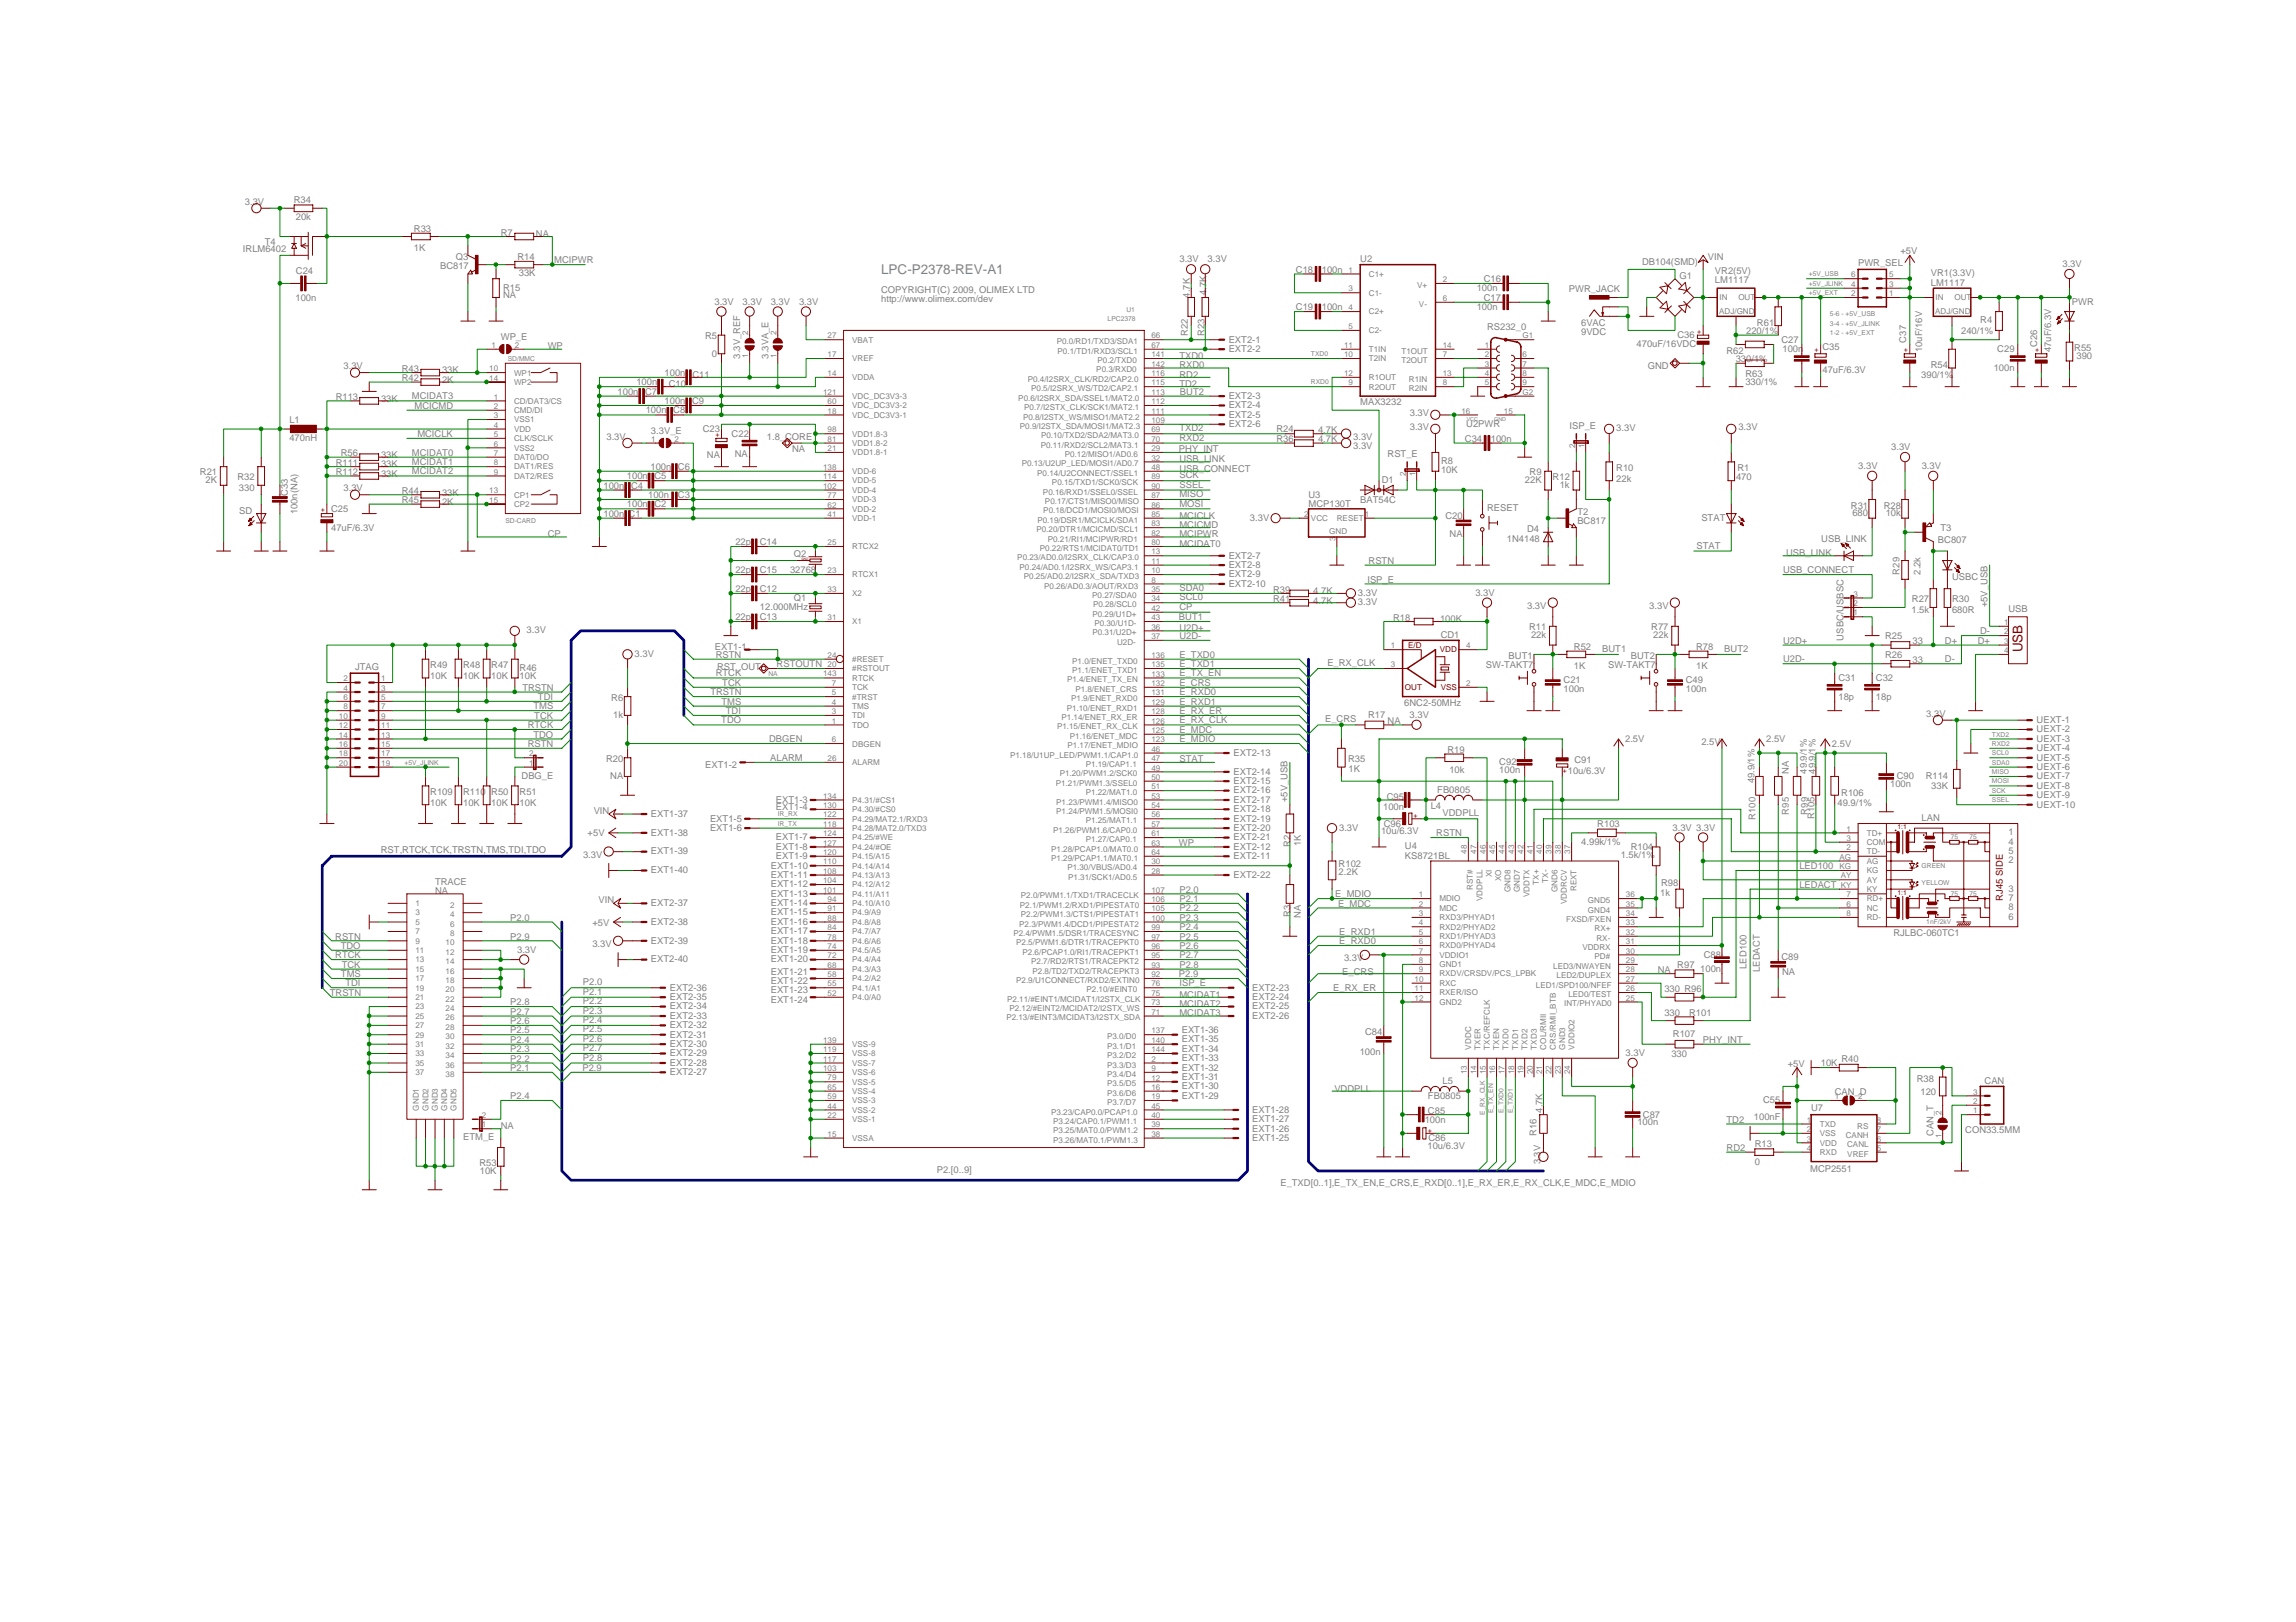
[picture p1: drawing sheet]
<svg xmlns="http://www.w3.org/2000/svg" width="297mm" height="210mm" viewBox="0 0 297 210" stroke-linecap="round" stroke-linejoin="round" font-family="sans-serif">
<defs><g id="words">
<text font-size="1.7" fill="#808080" x="114" y="35.5">LPC-P2378-REV-A1</text>
<text font-size="1.7" fill="#800000" x="261.7" y="84.4" transform="rotate(-90 261.7 84.4)">USB</text>
<g font-size="1.2" fill="#808080">
<text x="31.7" y="26.5">3.3V</text>
<text x="38" y="26.2">R34</text>
<text x="38.3" y="28.5">20k</text>
<text x="53.5" y="30">R33</text>
<text x="31.4" y="32.6">IRLM6402</text>
<text x="34.3" y="31.7">T4</text>
<text x="38.3" y="35.5">C24</text>
<text x="53.5" y="32.5">1K</text>
<text x="56.9" y="34.9">BC817</text>
<text x="59" y="33.6">Q3</text>
<text x="64.8" y="30.5">R7</text>
<text x="66.9" y="33.7">R14</text>
<text x="67.1" y="35.7">33K</text>
<text x="69.3" y="30.7">NA</text>
<text x="71.7" y="34">MCIPWR</text>
<text x="152.6" y="34">3.3V</text>
<text x="156.2" y="34">3.3V</text>
<text x="167.7" y="35.3">C18</text>
<text x="171" y="35.3">100n</text>
<text x="176" y="34">U2</text>
<text x="212.4" y="34.2">DB104(SMD)</text>
<text x="221" y="33.6">VIN</text>
<text x="221.9" y="35.5">VR2(5V)</text>
<text x="240.4" y="34.5">PWR_SEL</text>
<text x="245.9" y="32.9">+5V</text>
<text x="249.8" y="35.8">VR1(3.3V)</text>
<text x="266.8" y="34.5">3.3V</text>
<text x="38.2" y="38.9">100n</text>
<text x="65.1" y="37.6">R15</text>
<text x="65.1" y="38.6">NA</text>
<text x="92.4" y="39.4">3.3V</text>
<text x="96.1" y="39.4">3.3V</text>
<text x="99.7" y="39.4">3.3V</text>
<text x="103.4" y="39.4">3.3V</text>
<text x="114" y="37.9">COPYRIGHT(C) 2009, OLIMEX LTD</text>
<text x="114" y="39.1">http://www.olimex.com/dev</text>
<text x="153.9" y="38.5" transform="rotate(-90 153.9 38.5)">4.7K</text>
<text x="156.1" y="38.2" transform="rotate(-90 156.1 38.2)">4.7K</text>
<text x="167.7" y="40.1">C19</text>
<text x="171" y="40.1">100n</text>
<text x="191" y="37.7">100n</text>
<text x="191" y="40.1">100n</text>
<text x="192" y="36.5">C16</text>
<text x="192" y="38.9">C17</text>
<text x="203" y="37.8">PWR_JACK</text>
<text x="217.3" y="36.1">G1</text>
<text x="221.9" y="36.7">LM1117</text>
<text x="249.8" y="37">LM1117</text>
<text x="256.2" y="41.8">R4</text>
<text x="268.1" y="39.4">PWR</text>
<text x="44.4" y="47.8">3.3V</text>
<text x="64.8" y="44">WP_E</text>
<text x="70.9" y="45.2">WP</text>
<text x="91.2" y="43.9">R5</text>
<text x="92.1" y="46.2">0</text>
<text x="95.8" y="46.4" transform="rotate(-90 95.8 46.4)">3.3V_REF</text>
<text x="99.4" y="46.4" transform="rotate(-90 99.4 46.4)">3.3VA_E</text>
<text x="152.6" y="47.7">RXD0</text>
<text x="152.6" y="46.4">TXD0</text>
<text x="153.7" y="43.5" transform="rotate(-90 153.7 43.5)">R22</text>
<text x="155.8" y="43.5" transform="rotate(-90 155.8 43.5)">R23</text>
<text x="159" y="44.3">EXT2-1</text>
<text x="159" y="45.6">EXT2-2</text>
<text x="192.4" y="42.8">RS232_0</text>
<text x="204.6" y="42.1">6VAC</text>
<text x="204.6" y="43.4">9VDC</text>
<text x="211.7" y="45">470uF/16VDC</text>
<text x="213.2" y="47.8">GND</text>
<text x="217" y="43.7">C36</text>
<text x="223.3" y="45.8">R62</text>
<text x="224.6" y="46.8">330/1%</text>
<text x="225.9" y="43.2">220/1%</text>
<text x="227.3" y="42.2">R61</text>
<text x="230.5" y="44.4">C27</text>
<text x="230.6" y="45.6">100n</text>
<text x="235.8" y="45.3">C35</text>
<text x="246.6" y="44.3" transform="rotate(-90 246.6 44.3)">C37</text>
<text x="248.7" y="45.6" transform="rotate(-90 248.7 45.6)">10uF/16V</text>
<text x="249.8" y="47.6">R54</text>
<text x="253.7" y="43.2">240/1%</text>
<text x="258.4" y="45.6">C29</text>
<text x="263.6" y="44.9" transform="rotate(-90 263.6 44.9)">C26</text>
<text x="265.4" y="45.6" transform="rotate(-90 265.4 45.6)">47uF/6.3V</text>
<text x="268.3" y="45.4">R55</text>
<text x="268.6" y="46.5">390</text>
<text x="43.4" y="51.8">R113</text>
<text x="49.3" y="52">33K</text>
<text x="52" y="49.3">R42</text>
<text x="52" y="48.1">R43</text>
<text x="53.3" y="51.7">MCIDAT3</text>
<text x="53.6" y="52.9">MCICMD</text>
<text x="57.2" y="49.6">2K</text>
<text x="57.2" y="48.3">33K</text>
<text x="79.9" y="51.1">100n C7</text>
<text x="82.3" y="49.9">100n</text>
<text x="83.5" y="53.5">100n C8</text>
<text x="86" y="52.3">100n C9</text>
<text x="86" y="48.6">100n</text>
<text x="86.5" y="50.1">C10</text>
<text x="89.6" y="48.9">C11</text>
<text x="152.6" y="50.1">TD2</text>
<text x="152.6" y="48.9">RD2</text>
<text x="152.7" y="51.1">BUT2</text>
<text x="159" y="51.6">EXT2-3</text>
<text x="159" y="52.9">EXT2-4</text>
<text x="176" y="52.5">MAX3232</text>
<text x="182.4" y="53.9">3.3V</text>
<text x="225.8" y="49.8">330/1%</text>
<text x="225.8" y="48.8">R63</text>
<text x="235.8" y="48.3">47uF/6.3V</text>
<text x="248.6" y="48.9">390/1%</text>
<text x="257.9" y="48">100n</text>
<text x="37.4" y="57.1">470nH</text>
<text x="37.4" y="54.8">L1</text>
<text x="44.1" y="59.1">R56</text>
<text x="49.3" y="59.3">33K</text>
<text x="53.3" y="59">MCIDAT0</text>
<text x="54" y="56.6">MCICLK</text>
<text x="78.5" y="56.9">3.3V</text>
<text x="84.2" y="56.1">3.3V_E</text>
<text x="90.9" y="56">C23</text>
<text x="91.5" y="59.3">NA</text>
<text x="94.7" y="56.6">C22</text>
<text x="95.1" y="59.1">NA</text>
<text x="99.2" y="56.9">1.8_CORE</text>
<text x="102.5" y="58.5">NA</text>
<text x="152.5" y="58.4">PHY_INT</text>
<text x="152.6" y="57">RXD2</text>
<text x="152.6" y="55.8">TXD2</text>
<text x="152.6" y="59.8">USB_LINK</text>
<text x="159" y="54.1">EXT2-5</text>
<text x="159" y="55.3">EXT2-6</text>
<text x="165.1" y="57.2">R36</text>
<text x="165.1" y="56">R24</text>
<text x="170.5" y="57.2">4.7K</text>
<text x="170.5" y="56">4.7K</text>
<text x="175.1" y="56.9">3.3V</text>
<text x="175.1" y="58.1">3.3V</text>
<text x="179.5" y="59.2">RST_E</text>
<text x="182.4" y="55.7">3.3V</text>
<text x="189.5" y="57.1">C34</text>
<text x="189.7" y="55.3">U2PWR</text>
<text x="192.9" y="57.1">100n</text>
<text x="203" y="55.5">ISP_E</text>
<text x="209.1" y="55.8">3.3V</text>
<text x="224.9" y="55.7">3.3V</text>
<text x="244.7" y="58.3">3.3V</text>
<text x="25.9" y="61.5">R21</text>
<text x="26.6" y="62.6">2K</text>
<text x="30.7" y="62.2">R32</text>
<text x="30.9" y="63.5">330</text>
<text x="37.2" y="64.2" transform="rotate(-90 37.2 64.2)">C33</text>
<text x="43.4" y="60.3">R111</text>
<text x="43.4" y="61.5">R112</text>
<text x="44.4" y="63.6">3.3V</text>
<text x="49.3" y="60.5">33K</text>
<text x="49.3" y="61.7">33K</text>
<text x="52" y="63.9">R44</text>
<text x="52" y="65.1">R45</text>
<text x="53.3" y="60.2">MCIDAT1</text>
<text x="53.3" y="61.4">MCIDAT2</text>
<text x="57.2" y="64.1">33K</text>
<text x="57.2" y="65.3">2K</text>
<text x="78.1" y="63.2">100n C4</text>
<text x="81.1" y="65.7">100n C2</text>
<text x="81.1" y="62">100n C5</text>
<text x="83.9" y="64.5">100n</text>
<text x="84.2" y="60.8">100n C6</text>
<text x="87.7" y="64.5">C3</text>
<text x="152.6" y="64.3">MISO</text>
<text x="152.6" y="65.6">MOSI</text>
<text x="152.6" y="61.9">SCK</text>
<text x="152.6" y="63.1">SSEL</text>
<text x="152.6" y="61">USB_CONNECT</text>
<text x="169.3" y="65.6">MCP130T</text>
<text x="169.3" y="64.4">U3</text>
<text x="176" y="65.1">BAT54C</text>
<text x="178.8" y="62.6">D1</text>
<text x="186.4" y="60">R8</text>
<text x="186.4" y="61.2">10K</text>
<text x="197.3" y="62.6">22K</text>
<text x="197.9" y="61.5">R9</text>
<text x="200.9" y="62.1">R12</text>
<text x="201.8" y="63.2">1k</text>
<text x="209.1" y="61">R10</text>
<text x="209.1" y="62.3">22k</text>
<text x="224.6" y="62.1">470</text>
<text x="224.8" y="61">R1</text>
<text x="239.5" y="65.8">R31</text>
<text x="240.4" y="60.7">3.3V</text>
<text x="243.7" y="65.8">R28</text>
<text x="248.6" y="60.7">3.3V</text>
<text x="30.9" y="66.6">SD</text>
<text x="38.5" y="66.6" transform="rotate(-90 38.5 66.6)">100n(NA)</text>
<text x="42.8" y="68.7">47uF/6.3V</text>
<text x="42.8" y="66.2">C25</text>
<text x="70.9" y="69.5">CP</text>
<text x="78.1" y="66.9">100n C1</text>
<text x="95.1" y="70.5">22p</text>
<text x="98.3" y="70.5">C14</text>
<text x="152.6" y="70.8">MCIDAT0</text>
<text x="152.6" y="67.1">MCICLK</text>
<text x="152.6" y="68.3">MCICMD</text>
<text x="152.6" y="69.5">MCIPWR</text>
<text x="161.7" y="67.4">3.3V</text>
<text x="187" y="67.1">C20</text>
<text x="187.5" y="69.5">NA</text>
<text x="192.4" y="66.1">RESET</text>
<text x="194.9" y="70.1">1N4148</text>
<text x="197.6" y="68.9">D4</text>
<text x="204.1" y="66.6">T2</text>
<text x="204.1" y="67.9">BC817</text>
<text x="219.5" y="71.1">STAT</text>
<text x="220.1" y="67.5">STAT</text>
<text x="231.1" y="72">USB_LINK</text>
<text x="235.6" y="70.1">USB_LINK</text>
<text x="239.6" y="66.8">680</text>
<text x="244" y="66.8">10k</text>
<text x="250.7" y="70.3">BC807</text>
<text x="251" y="68.7">T3</text>
<text x="95.1" y="76.6">22p</text>
<text x="95.1" y="74.2">22p</text>
<text x="98.3" y="76.6">C12</text>
<text x="98.3" y="74.2">C15</text>
<text x="102.2" y="74.2">32768</text>
<text x="102.7" y="77.8">Q1</text>
<text x="102.7" y="72.1">Q2</text>
<text x="152.6" y="77.7">SCL0</text>
<text x="152.6" y="76.5">SDA0</text>
<text x="159" y="72.3">EXT2-7</text>
<text x="159" y="73.5">EXT2-8</text>
<text x="159" y="74.7">EXT2-9</text>
<text x="159" y="75.9">EXT2-10</text>
<text x="164.7" y="76.7">R39</text>
<text x="164.7" y="77.9">R41</text>
<text x="169.9" y="76.9">4.7K</text>
<text x="175.7" y="77.1">3.3V</text>
<text x="176.9" y="75.4">ISP_E</text>
<text x="177.1" y="73">RSTN</text>
<text x="190.9" y="77.1">3.3V</text>
<text x="230.7" y="74.2">USB_CONNECT</text>
<text x="245.8" y="74.4" transform="rotate(-90 245.8 74.4)">R29</text>
<text x="247.4" y="77.9">R27</text>
<text x="248.5" y="74.4" transform="rotate(-90 248.5 74.4)">2.2k</text>
<text x="252.5" y="75.1">USBC</text>
<text x="252.5" y="77.9">R30</text>
<text x="68.1" y="82">3.3V</text>
<text x="95.1" y="80.2">22p</text>
<text x="98.3" y="80.2">C13</text>
<text x="98.3" y="78.9">12.000MHz</text>
<text x="152.5" y="80.2">BUT1</text>
<text x="152.6" y="81.7">U2D+</text>
<text x="152.6" y="82.7">U2D-</text>
<text x="152.6" y="78.9">CP</text>
<text x="169.9" y="78.1">4.7K</text>
<text x="175.7" y="78.3">3.3V</text>
<text x="180.2" y="80.4">R18</text>
<text x="186.3" y="80.5">100K</text>
<text x="186.4" y="82.5">CD1</text>
<text x="197.6" y="78.8">3.3V</text>
<text x="197.8" y="81.5">R11</text>
<text x="198.1" y="82.6">22k</text>
<text x="213.4" y="78.8">3.3V</text>
<text x="213.6" y="81.5">R77</text>
<text x="213.9" y="82.6">22k</text>
<text x="230.7" y="83.3">U2D+</text>
<text x="238.5" y="82.9" transform="rotate(-90 238.5 82.9)">USBC/USBSC</text>
<text x="243.9" y="82.7">R25</text>
<text x="247.3" y="79.3">1.5k</text>
<text x="247.4" y="83.3">33</text>
<text x="251.6" y="83.3">D+</text>
<text x="252.5" y="79.3">680R</text>
<text x="255.9" y="83.3">D+</text>
<text x="256.2" y="82.1">D-</text>
<text x="257.1" y="78.6" transform="rotate(-90 257.1 78.6)">+5V_USB</text>
<text x="259.8" y="79.2">USB</text>
<text x="45.9" y="86.7">JTAG</text>
<text x="55.7" y="86.5">R49</text>
<text x="55.7" y="87.8">10K</text>
<text x="59.9" y="86.5">R48</text>
<text x="59.9" y="87.8">10K</text>
<text x="63.6" y="86.5">R47</text>
<text x="63.6" y="87.8">10K</text>
<text x="67.2" y="86.8">R46</text>
<text x="67.2" y="87.8">10K</text>
<text x="67.6" y="89.4">TRSTN</text>
<text x="82.1" y="85">3.3V</text>
<text x="91.9" y="90">TRSTN</text>
<text x="92.5" y="84.2">EXT1-1</text>
<text x="92.6" y="85.1">RSTN</text>
<text x="92.6" y="87.5">RTCK</text>
<text x="92.8" y="86.7">RST_OUT</text>
<text x="93.4" y="88.8">TCK</text>
<text x="100.5" y="86.3">RSTOUTN</text>
<text x="152.6" y="85.1">E_TXD0</text>
<text x="152.6" y="86.3">E_TXD1</text>
<text x="152.6" y="87.5">E_TX_EN</text>
<text x="152.6" y="88.8">E_CRS</text>
<text x="152.6" y="90">E_RXD0</text>
<text x="171.7" y="86.2">E_RX_CLK</text>
<text x="192.2" y="86.5">SW-TAKT7</text>
<text x="195.2" y="85.3">BUT1</text>
<text x="202.3" y="89.6">100n</text>
<text x="202.3" y="88.4">C21</text>
<text x="203.6" y="84.1">R52</text>
<text x="203.6" y="86.6">1K</text>
<text x="207.3" y="84.4">BUT1</text>
<text x="208" y="86.5">SW-TAKT7</text>
<text x="211" y="85.3">BUT2</text>
<text x="218.1" y="89.6">100n</text>
<text x="218.1" y="88.4">C49</text>
<text x="219.4" y="86.6">1K</text>
<text x="219.4" y="84.1">R78</text>
<text x="223.1" y="84.4">BUT2</text>
<text x="230.7" y="85.7">U2D-</text>
<text x="237.8" y="88.2">C31</text>
<text x="242.7" y="88.2">C32</text>
<text x="243.9" y="85.2">R26</text>
<text x="247.4" y="85.8">33</text>
<text x="251.6" y="85.7">D-</text>
<text x="68.3" y="94.2">RTCK</text>
<text x="69" y="95.4">TDO</text>
<text x="69" y="91.8">TMS</text>
<text x="69.1" y="93">TCK</text>
<text x="69.6" y="90.6">TDI</text>
<text x="79.1" y="90.7">R6</text>
<text x="79.3" y="92.9">1k</text>
<text x="93.3" y="93.6">TDO</text>
<text x="93.3" y="91.2">TMS</text>
<text x="93.9" y="92.4">TDI</text>
<text x="152.6" y="92.4">E_RX_ER</text>
<text x="152.6" y="94.8">E_MDC</text>
<text x="152.6" y="91.2">E_RXD1</text>
<text x="152.6" y="93.6">E_RX_CLK</text>
<text x="171.4" y="93.5">E_CRS</text>
<text x="177" y="92.9">R17</text>
<text x="179.5" y="93.7">NA</text>
<text x="181.7" y="91.4">6NC2-50MHz</text>
<text x="182.4" y="92.9">3.3V</text>
<text x="210.2" y="96">2.5V</text>
<text x="228.5" y="96">2.5V</text>
<text x="237.8" y="90.6">18p</text>
<text x="242.7" y="90.6">18p</text>
<text x="249.2" y="92.8">3.3V</text>
<text x="263.5" y="93.6">UEXT-1</text>
<text x="263.5" y="94.8">UEXT-2</text>
<text x="263.5" y="96">UEXT-3</text>
<text x="67.5" y="100.8">DBG_E</text>
<text x="68.3" y="96.7">RSTN</text>
<text x="78.4" y="98.6">R20</text>
<text x="78.9" y="100.9">NA</text>
<text x="91.2" y="99.4">EXT1-2</text>
<text x="99.5" y="96.1">DBGEN</text>
<text x="99.6" y="98.5">ALARM</text>
<text x="152.6" y="98.6">STAT</text>
<text x="152.6" y="96.1">E_MDIO</text>
<text x="159.6" y="97.8">EXT2-13</text>
<text x="159.6" y="100.2">EXT2-14</text>
<text x="159.6" y="101.5">EXT2-15</text>
<text x="174.4" y="98.6">R35</text>
<text x="174.5" y="99.9">1K</text>
<text x="187.3" y="97.5">R19</text>
<text x="187.5" y="100.1">10k</text>
<text x="194" y="99">C92</text>
<text x="194" y="100.1">100n</text>
<text x="202.8" y="100.2">10u/6.3V</text>
<text x="203.7" y="98.7">C91</text>
<text x="220.1" y="96.4">2.5V</text>
<text x="227" y="101.4" transform="rotate(-90 227 101.4)">49.9/1%</text>
<text x="231.4" y="100.1" transform="rotate(-90 231.4 100.1)">NA</text>
<text x="233.7" y="100.1" transform="rotate(-90 233.7 100.1)">49.9/1%</text>
<text x="234.9" y="100.1" transform="rotate(-90 234.9 100.1)">49.9/1%</text>
<text x="237" y="96.6">2.5V</text>
<text x="244.5" y="101.9">100n</text>
<text x="245.4" y="100.8">C90</text>
<text x="249.1" y="100.8">R114</text>
<text x="263.5" y="97.2">UEXT-4</text>
<text x="263.5" y="98.4">UEXT-5</text>
<text x="263.5" y="99.6">UEXT-6</text>
<text x="263.5" y="100.9">UEXT-7</text>
<text x="55.7" y="102.9">R109</text>
<text x="55.7" y="104.2">10K</text>
<text x="59.9" y="102.9">R110</text>
<text x="59.9" y="104.2">10K</text>
<text x="63.6" y="102.9">R50</text>
<text x="63.6" y="104.2">10K</text>
<text x="67.2" y="102.9">R51</text>
<text x="67.2" y="104.2">10K</text>
<text x="76.8" y="105.3">VIN</text>
<text x="84.2" y="105.7">EXT1-37</text>
<text x="91.9" y="106.3">EXT1-5</text>
<text x="91.9" y="107.5">EXT1-6</text>
<text x="100.4" y="103.9">EXT1-3</text>
<text x="100.4" y="104.8">EXT1-4</text>
<text x="159.6" y="102.7">EXT2-16</text>
<text x="159.6" y="103.9">EXT2-17</text>
<text x="159.6" y="105.1">EXT2-18</text>
<text x="159.6" y="106.3">EXT2-19</text>
<text x="159.6" y="107.5">EXT2-20</text>
<text x="166.6" y="103.8" transform="rotate(-90 166.6 103.8)">+5V_USB</text>
<text x="173.2" y="107.5">3.3V</text>
<text x="178.7" y="108">10u/6.3V</text>
<text x="178.9" y="104.8">100n</text>
<text x="179" y="107">C96</text>
<text x="179.4" y="103.6">C95</text>
<text x="185.1" y="104.7">L4</text>
<text x="185.9" y="102.7">FB0805</text>
<text x="186.6" y="105.6">VDDPLL</text>
<text x="206.6" y="107">R103</text>
<text x="216.4" y="107.5">3.3V 3.3V</text>
<text x="227.1" y="106.1" transform="rotate(-90 227.1 106.1)">R100</text>
<text x="231.4" y="105.4" transform="rotate(-90 231.4 105.4)">R95</text>
<text x="233.9" y="105.4" transform="rotate(-90 233.9 105.4)">R99</text>
<text x="234.7" y="106" transform="rotate(-90 234.7 106)">R105</text>
<text x="237.7" y="104.4">49.9/1%</text>
<text x="238.2" y="103">R106</text>
<text x="248.6" y="106.3">LAN</text>
<text x="249.8" y="102.1">33K</text>
<text x="263.5" y="102.1">UEXT-8</text>
<text x="263.5" y="103.3">UEXT-9</text>
<text x="263.5" y="104.5">UEXT-10</text>
<text x="49.3" y="110.4">RST,RTCK,TCK,TRSTN,TMS,TDI,TDO</text>
<text x="75.4" y="111">3.3V</text>
<text x="76" y="108.2">+5V</text>
<text x="84.2" y="108.1">EXT1-38</text>
<text x="84.2" y="110.6">EXT1-39</text>
<text x="84.2" y="113">EXT1-40</text>
<text x="99.7" y="112.4">EXT1-10</text>
<text x="99.7" y="113.6">EXT1-11</text>
<text x="100.4" y="108.8">EXT1-7</text>
<text x="100.4" y="110">EXT1-8</text>
<text x="100.4" y="111.2">EXT1-9</text>
<text x="152.5" y="109.5">WP</text>
<text x="159.6" y="111.2">EXT2-11</text>
<text x="159.6" y="110">EXT2-12</text>
<text x="159.6" y="108.8">EXT2-21</text>
<text x="159.6" y="113.6">EXT2-22</text>
<text x="167" y="109.6" transform="rotate(-90 167 109.6)">R2</text>
<text x="168.3" y="109.5" transform="rotate(-90 168.3 109.5)">1K</text>
<text x="173.2" y="113.2">2.2K</text>
<text x="173.2" y="112.2">R102</text>
<text x="181.8" y="109.9">U4</text>
<text x="181.8" y="111.1">KS8721BL</text>
<text x="185.8" y="108.2">RSTN</text>
<text x="204.6" y="109.4">4.99k/1%</text>
<text x="209.7" y="111.1">1.5k/1%</text>
<text x="211" y="110">R104</text>
<text x="232.8" y="112.5">LED100</text>
<text x="259.8" y="108.1">1</text>
<text x="259.8" y="109.3">4</text>
<text x="259.8" y="110.5">5</text>
<text x="259.8" y="111.7">2</text>
<text x="56.3" y="114.5">TRACE</text>
<text x="56.3" y="115.7">NA</text>
<text x="66" y="119.1">P2.0</text>
<text x="76.6" y="119.8">+5V</text>
<text x="77.4" y="116.9">VIN</text>
<text x="84.2" y="117.3">EXT2-37</text>
<text x="84.2" y="119.7">EXT2-38</text>
<text x="99.7" y="114.8">EXT1-12</text>
<text x="99.7" y="116">EXT1-13</text>
<text x="99.7" y="117.3">EXT1-14</text>
<text x="99.7" y="118.5">EXT1-15</text>
<text x="99.7" y="119.7">EXT1-16</text>
<text x="152.6" y="115.5">P2.0</text>
<text x="152.6" y="116.7">P2.1</text>
<text x="152.6" y="117.9">P2.2</text>
<text x="152.6" y="119.1">P2.3</text>
<text x="167" y="118.7" transform="rotate(-90 167 118.7)">R3</text>
<text x="168.3" y="118.8" transform="rotate(-90 168.3 118.8)">NA</text>
<text x="172.7" y="116.1">E_MDIO</text>
<text x="173.1" y="117.3">E_MDC</text>
<text x="214.8" y="115.9">1k</text>
<text x="214.9" y="114.6">R98</text>
<text x="232.8" y="114.9">LEDACT</text>
<text x="259.8" y="115.4">3</text>
<text x="259.8" y="116.6">7</text>
<text x="259.8" y="117.8">8</text>
<text x="259.8" y="119">6</text>
<text x="43.4" y="121.6">RSTN</text>
<text x="43.4" y="124">RTCK</text>
<text x="44.1" y="122.8">TDO</text>
<text x="44.2" y="125.2">TCK</text>
<text x="66" y="121.6">P2.9</text>
<text x="66.9" y="123.3">3.3V</text>
<text x="76.6" y="122.5">3.3V</text>
<text x="84.2" y="122.1">EXT2-39</text>
<text x="84.2" y="124.5">EXT2-40</text>
<text x="99.7" y="120.9">EXT1-17</text>
<text x="99.7" y="122.1">EXT1-18</text>
<text x="99.7" y="123.3">EXT1-19</text>
<text x="99.7" y="124.5">EXT1-20</text>
<text x="152.6" y="120.4">P2.4</text>
<text x="152.6" y="121.6">P2.5</text>
<text x="152.6" y="122.8">P2.6</text>
<text x="152.6" y="124">P2.7</text>
<text x="152.6" y="125.2">P2.8</text>
<text x="173.3" y="122.2">E_RXD0</text>
<text x="173.3" y="121">E_RXD1</text>
<text x="173.9" y="124.4">3.3V</text>
<text x="214.5" y="125.9">NA</text>
<text x="217" y="125.3">R97</text>
<text x="220" y="125.8">100n</text>
<text x="220.4" y="123.9">C88</text>
<text x="226" y="125.4" transform="rotate(-90 226 125.4)">LED100</text>
<text x="227.7" y="125.8" transform="rotate(-90 227.7 125.8)">LEDACT</text>
<text x="230.5" y="124.2">C89</text>
<text x="245" y="121.2">RJLBC-060TC1</text>
<text x="42.7" y="128.9">TRSTN</text>
<text x="44.1" y="126.4">TMS</text>
<text x="44.7" y="127.7">TDI</text>
<text x="66" y="131.3">P2.7</text>
<text x="66" y="130.1">P2.8</text>
<text x="75.4" y="127.5">P2.0</text>
<text x="75.4" y="128.7">P2.1</text>
<text x="75.4" y="130">P2.2</text>
<text x="75.4" y="131.2">P2.3</text>
<text x="86.7" y="131.8">EXT2-33</text>
<text x="86.7" y="130.6">EXT2-34</text>
<text x="86.7" y="129.4">EXT2-35</text>
<text x="86.7" y="128.2">EXT2-36</text>
<text x="99.7" y="126.1">EXT1-21</text>
<text x="99.7" y="127.3">EXT1-22</text>
<text x="99.7" y="128.5">EXT1-23</text>
<text x="99.7" y="129.8">EXT1-24</text>
<text x="152.5" y="126.5">P2.9</text>
<text x="152.6" y="129.1">MCIDAT1</text>
<text x="152.6" y="130.3">MCIDAT2</text>
<text x="152.6" y="131.5">MCIDAT3</text>
<text x="152.6" y="127.7">ISP_E</text>
<text x="162" y="128.2">EXT2-23</text>
<text x="162" y="129.4">EXT2-24</text>
<text x="162" y="130.6">EXT2-25</text>
<text x="162" y="131.8">EXT2-26</text>
<text x="172.5" y="128.2">E_RX_ER</text>
<text x="173.6" y="126.1">E_CRS</text>
<text x="215.3" y="128.4">330 R96</text>
<text x="215.3" y="131.5">330</text>
<text x="218.5" y="131.5">R101</text>
<text x="230.5" y="126.2">NA</text>
<text x="66" y="137.4">P2.2</text>
<text x="66" y="136.2">P2.3</text>
<text x="66" y="134.9">P2.4</text>
<text x="66" y="133.7">P2.5</text>
<text x="66" y="132.5">P2.6</text>
<text x="75.4" y="132.4">P2.4</text>
<text x="75.4" y="133.6">P2.5</text>
<text x="75.4" y="134.8">P2.6</text>
<text x="75.4" y="136">P2.7</text>
<text x="75.4" y="137.2">P2.8</text>
<text x="86.7" y="137.9">EXT2-28</text>
<text x="86.7" y="136.7">EXT2-29</text>
<text x="86.7" y="135.5">EXT2-30</text>
<text x="86.7" y="134.3">EXT2-31</text>
<text x="86.7" y="133.1">EXT2-32</text>
<text x="152.9" y="137.3">EXT1-33</text>
<text x="152.9" y="136.1">EXT1-34</text>
<text x="152.9" y="134.9">EXT1-35</text>
<text x="152.9" y="133.7">EXT1-36</text>
<text x="175.9" y="136.5">100n</text>
<text x="176.6" y="134">C84</text>
<text x="210.3" y="136.7">3.3V</text>
<text x="216.2" y="136.8">330</text>
<text x="216.4" y="134.2">R107</text>
<text x="220.3" y="134.9">PHY_INT</text>
<text x="235.6" y="137.9">10K</text>
<text x="238.2" y="137.5">R40</text>
<text x="66" y="138.6">P2.1</text>
<text x="66" y="142.2">P2.4</text>
<text x="75.3" y="138.5">P2.9</text>
<text x="86.7" y="139.1">EXT2-27</text>
<text x="152.9" y="142.2">EXT1-29</text>
<text x="152.9" y="141">EXT1-30</text>
<text x="152.9" y="139.7">EXT1-31</text>
<text x="152.9" y="138.5">EXT1-32</text>
<text x="162" y="144">EXT1-28</text>
<text x="172.6" y="141.4">VDDPLL</text>
<text x="184.7" y="142.2">FB0805</text>
<text x="186.6" y="140.3">L5</text>
<text x="199.6" y="144" transform="rotate(-90 199.6 144)">4.7K</text>
<text x="228.1" y="142.8">C55</text>
<text x="231.3" y="138">+5V</text>
<text x="234.3" y="143.8">U7</text>
<text x="237.4" y="141.7">CAN_D</text>
<text x="248" y="140">R38</text>
<text x="248.5" y="141.7">120</text>
<text x="256.7" y="140.2">CAN</text>
<text x="59.9" y="147.6">ETM_E</text>
<text x="64.8" y="146.1">NA</text>
<text x="162" y="147.6">EXT1-25</text>
<text x="162" y="146.4">EXT1-26</text>
<text x="162" y="145.2">EXT1-27</text>
<text x="184.3" y="145.3">100n</text>
<text x="184.7" y="148.7">10u/6.3V</text>
<text x="184.7" y="144.2">C85</text>
<text x="184.8" y="147.7">C86</text>
<text x="198.8" y="147" transform="rotate(-90 198.8 147)">R16</text>
<text x="211.8" y="145.6">100n</text>
<text x="212.6" y="144.7">C87</text>
<text x="223.4" y="145.3">TD2</text>
<text x="223.4" y="148.9">RD2</text>
<text x="226.9" y="144.9">100nF</text>
<text x="227" y="148.5">R13</text>
<text x="250.1" y="147" transform="rotate(-90 250.1 147)">CAN_T</text>
<text x="254.3" y="146.7">CON33.5MM</text>
<text x="62" y="150.9">R53</text>
<text x="62.1" y="151.9">10K</text>
<text x="121.2" y="151.8">P2.[0..9]</text>
<text x="165.6" y="153.5">E_TXD[0..1],E_TX_EN,E_CRS,E_RXD[0..1],E_RX_ER,E_RX_CLK,E_MDC,E_MDIO</text>
<text x="199.3" y="150.7" transform="rotate(-90 199.3 150.7)">3.3V</text>
<text x="227" y="150.7">0</text>
<text x="234.2" y="151.7">MCP2551</text>
</g>
<text font-size="1.2" fill="#800000" x="259.1" y="116.6" transform="rotate(-90 259.1 116.6)">RJ45 SIDE</text>
<g font-size="1" fill="#808080">
<text x="174.5" y="35.3">1</text>
<text x="177.1" y="35.8">C1+</text>
<text x="239.5" y="35.9">6</text>
<text x="244.4" y="35.9">5</text>
<text x="174.5" y="37.7">3</text>
<text x="174.5" y="40.2">4</text>
<text x="177.1" y="38.2">C1-</text>
<text x="177.1" y="40.7">C2+</text>
<text x="183.3" y="37.3">V+</text>
<text x="183.6" y="39.7">V-</text>
<text x="186.6" y="36.5">2</text>
<text x="186.6" y="38.9">6</text>
<text x="222.4" y="40.6">ADJ/GND</text>
<text x="222.5" y="38.8">IN</text>
<text x="224.9" y="38.8">OUT</text>
<text x="239.5" y="38.3">2</text>
<text x="239.5" y="37.1">4</text>
<text x="244.4" y="38.3">1</text>
<text x="244.4" y="37.1">3</text>
<text x="250.4" y="40.6">ADJ/GND</text>
<text x="250.4" y="38.8">IN</text>
<text x="252.9" y="38.8">OUT</text>
<text x="63.6" y="45">1</text>
<text x="66.6" y="45">2</text>
<text x="96.8" y="46.4" transform="rotate(-90 96.8 46.4)">1</text>
<text x="96.8" y="43.4" transform="rotate(-90 96.8 43.4)">2</text>
<text x="100.5" y="46.4" transform="rotate(-90 100.5 46.4)">1</text>
<text x="100.5" y="43.4" transform="rotate(-90 100.5 43.4)">2</text>
<text x="107.1" y="43.8">27</text>
<text x="107.1" y="46.2">17</text>
<text x="110.3" y="44.3">VBAT</text>
<text x="110.3" y="46.8">VREF</text>
<text x="136.7" y="44.6">P0.0/RD1/TXD3/SDA1</text>
<text x="136.8" y="45.8">P0.1/TD1/RXD3/SCL1</text>
<text x="142" y="47">P0.2/TXD0</text>
<text x="149" y="43.8">66</text>
<text x="149" y="45">67</text>
<text x="149" y="46.2">141</text>
<text x="149" y="47.5">142</text>
<text x="173.9" y="46.2">10</text>
<text x="173.9" y="45">11</text>
<text x="174.5" y="42.6">5</text>
<text x="177.1" y="46.8">T2IN</text>
<text x="177.1" y="45.6">T1IN</text>
<text x="177.1" y="43.1">C2-</text>
<text x="181.3" y="47">T2OUT</text>
<text x="181.3" y="45.8">T1OUT</text>
<text x="186.6" y="46.2">7</text>
<text x="186.6" y="45">14</text>
<text x="192.1" y="45">1</text>
<text x="192.1" y="46.2">2</text>
<text x="192.1" y="47.5">3</text>
<text x="197" y="46.2">6</text>
<text x="197" y="47.5">7</text>
<text x="197" y="43.8">G1</text>
<text x="63.3" y="48">10</text>
<text x="63.3" y="49.3">14</text>
<text x="63.9" y="51.7">1</text>
<text x="63.9" y="52.9">2</text>
<text x="66.5" y="52.2">CD/DAT3/CS</text>
<text x="66.5" y="53.4">CMD/DI</text>
<text x="66.5" y="48.6">WP1</text>
<text x="66.5" y="49.8">WP2</text>
<text x="106.5" y="51.1">121</text>
<text x="107.1" y="53.5">18</text>
<text x="107.1" y="52.3">60</text>
<text x="107.1" y="48.7">14</text>
<text x="110.3" y="52.9">VDC_DC3V3-2</text>
<text x="110.3" y="51.6">VDC_DC3V3-3</text>
<text x="110.3" y="49.2">VDDA</text>
<text x="131.7" y="51.9">P0.6/I2SRX_SDA/SSEL1/MAT2.0</text>
<text x="132.5" y="53.1">P0.7/I2STX_CLK/SCK1/MAT2.1</text>
<text x="133" y="49.4">P0.4/I2SRX_CLK/RD2/CAP2.0</text>
<text x="133.4" y="50.6">P0.5/I2SRX_WS/TD2/CAP2.1</text>
<text x="141.8" y="48.2">P0.3/RXD0</text>
<text x="149" y="48.7">116</text>
<text x="149" y="49.9">115</text>
<text x="149" y="51.1">113</text>
<text x="149" y="52.3">112</text>
<text x="149" y="53.5">111</text>
<text x="173.9" y="48.7">12</text>
<text x="174.5" y="49.9">9</text>
<text x="177.1" y="50.4">R2OUT</text>
<text x="177.1" y="49.2">R1OUT</text>
<text x="182.3" y="50.6">R2IN</text>
<text x="182.3" y="49.4">R1IN</text>
<text x="186.6" y="49.9">8</text>
<text x="186.6" y="48.7">13</text>
<text x="189.1" y="53.5">16</text>
<text x="192.1" y="48.7">4</text>
<text x="192.1" y="49.9">5</text>
<text x="194.6" y="53.5">15</text>
<text x="197" y="48.7">8</text>
<text x="197" y="49.9">9</text>
<text x="197" y="51.1">G2</text>
<text x="63.9" y="56.6">5</text>
<text x="63.9" y="59">7</text>
<text x="63.9" y="55.4">4</text>
<text x="63.9" y="54.1">3</text>
<text x="63.9" y="57.8">6</text>
<text x="66.5" y="57.1">CLK/SCLK</text>
<text x="66.5" y="59.5">DAT0/DO</text>
<text x="66.5" y="55.9">VDD</text>
<text x="66.5" y="54.7">VSS1</text>
<text x="66.5" y="58.3">VSS2</text>
<text x="84.3" y="57.2">1</text>
<text x="87.3" y="57.2">2</text>
<text x="107.1" y="58.4">21</text>
<text x="107.1" y="57.2">81</text>
<text x="107.1" y="56">98</text>
<text x="110.3" y="54.1">VDC_DC3V3-1</text>
<text x="110.3" y="58.9">VDD1.8-1</text>
<text x="110.3" y="57.7">VDD1.8-2</text>
<text x="110.3" y="56.5">VDD1.8-3</text>
<text x="131.9" y="55.5">P0.9/I2STX_SDA/MOSI1/MAT2.3</text>
<text x="132.4" y="54.3">P0.8/I2STX_WS/MISO1/MAT2.2</text>
<text x="134.6" y="57.9">P0.11/RXD2/SCL2/MAT3.1</text>
<text x="134.7" y="56.7">P0.10/TXD2/SDA2/MAT3.0</text>
<text x="137.7" y="59.1">P0.12/MISO1/AD0.6</text>
<text x="149" y="54.7">109</text>
<text x="149" y="56">69</text>
<text x="149" y="57.2">70</text>
<text x="149" y="58.4">29</text>
<text x="149" y="59.6">32</text>
<text x="203.8" y="57.9" transform="rotate(-90 203.8 57.9)">2</text>
<text x="205" y="57.9" transform="rotate(-90 205 57.9)">1</text>
<text x="63.3" y="63.9">13</text>
<text x="63.3" y="65.1">15</text>
<text x="63.9" y="60.2">8</text>
<text x="63.9" y="61.4">9</text>
<text x="66.5" y="64.4">CP1</text>
<text x="66.5" y="65.6">CP2</text>
<text x="66.5" y="60.7">DAT1/RES</text>
<text x="66.5" y="62">DAT2/RES</text>
<text x="106.5" y="63.2">102</text>
<text x="106.5" y="62">114</text>
<text x="106.5" y="60.8">138</text>
<text x="107.1" y="65.7">62</text>
<text x="107.1" y="64.5">77</text>
<text x="110.3" y="65">VDD-3</text>
<text x="110.3" y="63.8">VDD-4</text>
<text x="110.3" y="62.6">VDD-5</text>
<text x="110.3" y="61.3">VDD-6</text>
<text x="132.2" y="60.4">P0.13/U2UP_LED/MOSI1/AD0.7</text>
<text x="134.2" y="61.6">P0.14/U2CONNECT/SSEL1</text>
<text x="134.9" y="64">P0.16/RXD1/SSEL0/SSEL</text>
<text x="135.2" y="65.2">P0.17/CTS1/MISO0/MISO</text>
<text x="136.1" y="62.8">P0.15/TXD1/SCK0/SCK</text>
<text x="149" y="60.8">48</text>
<text x="149" y="62">89</text>
<text x="149" y="63.2">90</text>
<text x="149" y="64.5">87</text>
<text x="149" y="65.7">86</text>
<text x="181.9" y="61.6" transform="rotate(-90 181.9 61.6)">2</text>
<text x="183.1" y="61.6" transform="rotate(-90 183.1 61.6)">1</text>
<text x="107.1" y="70.5">25</text>
<text x="107.1" y="66.9">41</text>
<text x="110.3" y="71.1">RTCX2</text>
<text x="110.3" y="67.4">VDD-1</text>
<text x="110.3" y="66.2">VDD-2</text>
<text x="134.1" y="68.9">P0.20/DTR1/MCICMD/SCL1</text>
<text x="134.2" y="67.6">P0.19/DSR1/MCICLK/SDA1</text>
<text x="134.5" y="71.3">P0.22/RTS1/MCIDAT0/TD1</text>
<text x="135" y="66.4">P0.18/DCD1/MOSI0/MOSI</text>
<text x="135.5" y="70.1">P0.21/RI1/MCIPWR/RD1</text>
<text x="149" y="66.9">85</text>
<text x="149" y="68.1">83</text>
<text x="149" y="69.3">82</text>
<text x="149" y="70.5">80</text>
<text x="149" y="71.8">13</text>
<text x="168.7" y="66.9">2</text>
<text x="169.6" y="67.4">VCC</text>
<text x="172" y="69.1">GND</text>
<text x="172.8" y="70.1" transform="rotate(-90 172.8 70.1)">3</text>
<text x="172.9" y="67.4">RESET</text>
<text x="176.6" y="66.9">1</text>
<text x="107.1" y="74.2">23</text>
<text x="107.1" y="76.6">33</text>
<text x="110.3" y="74.7">RTCX1</text>
<text x="110.3" y="77.2">X2</text>
<text x="131.6" y="72.5">P0.23/AD0.0/I2SRX_CLK/CAP3.0</text>
<text x="131.9" y="73.7">P0.24/AD0.1/I2SRX_WS/CAP3.1</text>
<text x="132.5" y="75">P0.25/AD0.2/I2SRX_SDA/TXD3</text>
<text x="135.1" y="76.2">P0.26/AD0.3/AOUT/RXD3</text>
<text x="141.3" y="77.4">P0.27/SDA0</text>
<text x="149" y="73">11</text>
<text x="149" y="74.2">10</text>
<text x="149" y="75.4">8</text>
<text x="149" y="76.6">35</text>
<text x="149" y="77.8">34</text>
<text x="239.8" y="77.2">3</text>
<text x="107.1" y="80.3">31</text>
<text x="110.3" y="80.8">X1</text>
<text x="141.3" y="79.8">P0.29/U1D+</text>
<text x="141.3" y="82.2">P0.31/U2D+</text>
<text x="141.4" y="78.6">P0.28/SCL0</text>
<text x="141.6" y="81">P0.30/U1D-</text>
<text x="144.5" y="83.5">U2D-</text>
<text x="149" y="79.1">42</text>
<text x="149" y="80.3">43</text>
<text x="149" y="81.5">36</text>
<text x="149" y="82.7">37</text>
<text x="179.9" y="83.9">1</text>
<text x="189.7" y="83.9">4</text>
<text x="239.8" y="79.7">1</text>
<text x="239.8" y="78.4">2</text>
<text x="259.3" y="80.9">1</text>
<text x="259.3" y="82.1">2</text>
<text x="259.3" y="83.3">3</text>
<text x="44.4" y="88.2">2</text>
<text x="44.4" y="89.4">4</text>
<text x="49.3" y="88.2">1</text>
<text x="49.3" y="89.4">3</text>
<text x="106.5" y="87.5">143</text>
<text x="107.1" y="85.1">24</text>
<text x="107.1" y="86.3">20</text>
<text x="107.6" y="90">5</text>
<text x="107.6" y="88.8">7</text>
<text x="110.3" y="85.7">#RESET</text>
<text x="110.3" y="86.9">#RSTOUT</text>
<text x="110.3" y="88.1">RTCK</text>
<text x="110.3" y="89.3">TCK</text>
<text x="138" y="88.3">P1.4/ENET_TX_EN</text>
<text x="138.7" y="85.9">P1.0/ENET_TXD0</text>
<text x="138.7" y="87.1">P1.1/ENET_TXD1</text>
<text x="139.1" y="89.5">P1.8/ENET_CRS</text>
<text x="149" y="85.1">136</text>
<text x="149" y="86.3">135</text>
<text x="149" y="87.5">133</text>
<text x="149" y="88.8">132</text>
<text x="149" y="90">131</text>
<text x="179.9" y="86.3">3</text>
<text x="189.7" y="88.8">2</text>
<text x="259.3" y="84.5">4</text>
<text x="43.9" y="93">10</text>
<text x="43.9" y="94.2">12</text>
<text x="43.9" y="95.5">14</text>
<text x="44.4" y="90.6">6</text>
<text x="44.4" y="91.8">8</text>
<text x="49.3" y="90.6">5</text>
<text x="49.3" y="91.8">7</text>
<text x="49.3" y="93">9</text>
<text x="49.3" y="94.2">11</text>
<text x="49.3" y="95.5">13</text>
<text x="107.6" y="92.4">3</text>
<text x="107.6" y="93.6">1</text>
<text x="107.6" y="91.2">4</text>
<text x="110.3" y="90.5">#TRST</text>
<text x="110.3" y="92.9">TDI</text>
<text x="110.3" y="94.2">TDO</text>
<text x="110.3" y="91.7">TMS</text>
<text x="136.8" y="94.4">P1.15/ENET_RX_CLK</text>
<text x="137.3" y="93.2">P1.14/ENET_RX_ER</text>
<text x="138" y="92">P1.10/ENET_RXD1</text>
<text x="138.4" y="95.6">P1.16/ENET_MDC</text>
<text x="138.6" y="90.7">P1.9/ENET_RXD0</text>
<text x="149" y="91.2">129</text>
<text x="149" y="92.4">128</text>
<text x="149" y="93.6">126</text>
<text x="149" y="94.8">125</text>
<text x="43.9" y="96.7">16</text>
<text x="43.9" y="97.9">18</text>
<text x="43.9" y="99.1">20</text>
<text x="49.3" y="96.7">15</text>
<text x="49.3" y="97.9">17</text>
<text x="49.3" y="99.1">19</text>
<text x="68.5" y="99.1">1</text>
<text x="68.5" y="97.9">2</text>
<text x="107.1" y="98.5">26</text>
<text x="107.6" y="96.1">6</text>
<text x="110.3" y="99">ALARM</text>
<text x="110.3" y="96.6">DBGEN</text>
<text x="130.7" y="98">P1.18/U1UP_LED/PWM1.1/CAP1.0</text>
<text x="136.6" y="101.7">P1.21/PWM1.3/SSEL0</text>
<text x="137.1" y="100.5">P1.20/PWM1.2/SCK0</text>
<text x="138.1" y="96.8">P1.17/ENET_MDIO</text>
<text x="140.5" y="99.3">P1.19/CAP1.1</text>
<text x="149" y="96.1">123</text>
<text x="149" y="97.3">46</text>
<text x="149" y="98.5">47</text>
<text x="149" y="99.7">49</text>
<text x="149" y="100.9">50</text>
<text x="106.5" y="107">118</text>
<text x="106.5" y="105.8">122</text>
<text x="106.5" y="104.6">130</text>
<text x="106.5" y="103.4">134</text>
<text x="110.3" y="107.5">P4.28/MAT2.0/TXD3</text>
<text x="110.3" y="106.3">P4.29/MAT2.1/RXD3</text>
<text x="110.3" y="105.1">P4.30/#CS0</text>
<text x="110.3" y="103.9">P4.31/#CS1</text>
<text x="136.2" y="107.8">P1.26/PWM1.6/CAP0.0</text>
<text x="136.6" y="104.1">P1.23/PWM1.4/MISO0</text>
<text x="136.6" y="105.3">P1.24/PWM1.5/MOSI0</text>
<text x="140.5" y="102.9">P1.22/MAT1.0</text>
<text x="140.5" y="106.6">P1.25/MAT1.1</text>
<text x="149" y="102.2">51</text>
<text x="149" y="103.4">53</text>
<text x="149" y="104.6">54</text>
<text x="149" y="105.8">56</text>
<text x="149" y="107">57</text>
<text x="238.9" y="107.6">1</text>
<text x="106.5" y="111.9">110</text>
<text x="106.5" y="110.6">120</text>
<text x="106.5" y="109.4">127</text>
<text x="106.5" y="108.2">124</text>
<text x="106.5" y="113.1">108</text>
<text x="110.3" y="112.4">P4.14/A14</text>
<text x="110.3" y="111.2">P4.15/A15</text>
<text x="110.3" y="110">P4.24/#OE</text>
<text x="110.3" y="108.8">P4.25/#WE</text>
<text x="110.3" y="113.6">P4.13/A13</text>
<text x="136" y="110.2">P1.28/PCAP1.0/MAT0.0</text>
<text x="136" y="111.4">P1.29/PCAP1.1/MAT0.1</text>
<text x="138.1" y="112.6">P1.30/VBUS/AD0.4</text>
<text x="138.2" y="113.8">P1.31/SCK1/AD0.5</text>
<text x="140.5" y="109">P1.27/CAP0.1</text>
<text x="149" y="108.2">61</text>
<text x="149" y="109.4">63</text>
<text x="149" y="110.6">64</text>
<text x="149" y="111.9">30</text>
<text x="149" y="113.1">28</text>
<text x="189.8" y="110.5" transform="rotate(-90 189.8 110.5)">48</text>
<text x="191" y="110.5" transform="rotate(-90 191 110.5)">47</text>
<text x="192.2" y="110.5" transform="rotate(-90 192.2 110.5)">46</text>
<text x="193" y="113.5" transform="rotate(-90 193 113.5)">XI</text>
<text x="193.4" y="110.5" transform="rotate(-90 193.4 110.5)">45</text>
<text x="194.6" y="110.5" transform="rotate(-90 194.6 110.5)">44</text>
<text x="195.9" y="110.5" transform="rotate(-90 195.9 110.5)">43</text>
<text x="197.1" y="110.5" transform="rotate(-90 197.1 110.5)">42</text>
<text x="198.3" y="110.5" transform="rotate(-90 198.3 110.5)">41</text>
<text x="199.5" y="110.5" transform="rotate(-90 199.5 110.5)">40</text>
<text x="200.7" y="110.5" transform="rotate(-90 200.7 110.5)">39</text>
<text x="201.9" y="110.5" transform="rotate(-90 201.9 110.5)">38</text>
<text x="203.2" y="110.5" transform="rotate(-90 203.2 110.5)">37</text>
<text x="238" y="111.3">AG</text>
<text x="238" y="112.5">KG</text>
<text x="238.1" y="113.7">AY</text>
<text x="238.9" y="108.8">3</text>
<text x="238.9" y="110">2</text>
<text x="241.5" y="111.8">AG</text>
<text x="241.5" y="109.4">COM</text>
<text x="241.5" y="113">KG</text>
<text x="241.5" y="108.1">TD+</text>
<text x="241.5" y="110.6">TD-</text>
<text x="53.7" y="117.3">1</text>
<text x="53.7" y="118.5">3</text>
<text x="53.7" y="119.7">5</text>
<text x="58.2" y="117.5">2</text>
<text x="58.2" y="118.7">4</text>
<text x="58.2" y="119.9">6</text>
<text x="106.5" y="115.5">101</text>
<text x="106.5" y="114.3">104</text>
<text x="107.1" y="119.1">88</text>
<text x="107.1" y="117.9">91</text>
<text x="107.1" y="116.7">94</text>
<text x="110.3" y="119.7">P4.8/A8</text>
<text x="110.3" y="118.5">P4.9/A9</text>
<text x="110.3" y="117.3">P4.10/A10</text>
<text x="110.3" y="116">P4.11/A11</text>
<text x="110.3" y="114.8">P4.12/A12</text>
<text x="131.9" y="119.9">P2.3/PWM1.4/DCD1/PIPESTAT2</text>
<text x="131.9" y="117.5">P2.1/PWM1.2/RXD1/PIPESTAT0</text>
<text x="132.1" y="116.3">P2.0/PWM1.1/TXD1/TRACECLK</text>
<text x="132.1" y="118.7">P2.2/PWM1.3/CTS1/PIPESTAT1</text>
<text x="149" y="115.5">107</text>
<text x="149" y="116.7">106</text>
<text x="149" y="117.9">105</text>
<text x="149" y="119.1">100</text>
<text x="183.6" y="119.8">4</text>
<text x="183.6" y="118.6">3</text>
<text x="183.6" y="117.3">2</text>
<text x="183.6" y="116.1">1</text>
<text x="186.2" y="119.1">RXD3/PHYAD1</text>
<text x="186.2" y="117.9">MDC</text>
<text x="186.2" y="116.6">MDIO</text>
<text x="190.6" y="115.2" transform="rotate(-90 190.6 115.2)">RST#</text>
<text x="191.8" y="116.6" transform="rotate(-90 191.8 116.6)">VDDPLL</text>
<text x="194.2" y="114" transform="rotate(-90 194.2 114)">XO</text>
<text x="195.4" y="115.4" transform="rotate(-90 195.4 115.4)">GND8</text>
<text x="196.6" y="115.4" transform="rotate(-90 196.6 115.4)">GND7</text>
<text x="197.9" y="116.1" transform="rotate(-90 197.9 116.1)">VDDTX</text>
<text x="199.1" y="114.5" transform="rotate(-90 199.1 114.5)">TX+</text>
<text x="200.3" y="114.2" transform="rotate(-90 200.3 114.2)">TX-</text>
<text x="201.5" y="115.4" transform="rotate(-90 201.5 115.4)">GND6</text>
<text x="202.6" y="119.3">FXSD/FXEN</text>
<text x="202.7" y="117" transform="rotate(-90 202.7 117)">VDDRCV</text>
<text x="203.9" y="115.3" transform="rotate(-90 203.9 115.3)">REXT</text>
<text x="205.4" y="118.1">GND4</text>
<text x="205.4" y="116.9">GND5</text>
<text x="210.4" y="118.6">34</text>
<text x="210.4" y="119.8">33</text>
<text x="210.4" y="117.3">35</text>
<text x="210.4" y="116.1">36</text>
<text x="238.1" y="114.9">KY</text>
<text x="238.9" y="117.3">6</text>
<text x="238.9" y="116.1">7</text>
<text x="238.9" y="118.6">8</text>
<text x="241.5" y="114.2">AY</text>
<text x="241.5" y="115.4">KY</text>
<text x="241.5" y="117.9">NC</text>
<text x="241.5" y="116.6">RD+</text>
<text x="241.5" y="119.1">RD-</text>
<text x="53.7" y="120.9">7</text>
<text x="53.7" y="122.1">9</text>
<text x="53.7" y="123.3">11</text>
<text x="53.7" y="124.5">13</text>
<text x="53.7" y="125.8">15</text>
<text x="57.7" y="122.3">10</text>
<text x="57.7" y="123.5">12</text>
<text x="57.7" y="124.8">14</text>
<text x="57.7" y="126">16</text>
<text x="58.2" y="121.1">8</text>
<text x="107.1" y="125.2">68</text>
<text x="107.1" y="124">72</text>
<text x="107.1" y="122.8">74</text>
<text x="107.1" y="121.6">78</text>
<text x="107.1" y="120.4">84</text>
<text x="110.3" y="125.8">P4.3/A3</text>
<text x="110.3" y="124.5">P4.4/A4</text>
<text x="110.3" y="123.3">P4.5/A5</text>
<text x="110.3" y="122.1">P4.6/A6</text>
<text x="110.3" y="120.9">P4.7/A7</text>
<text x="131.1" y="121.1">P2.4/PWM1.5/DSR1/TRACESYNC</text>
<text x="131.5" y="122.3">P2.5/PWM1.6/DTR1/TRACEPKT0</text>
<text x="132.3" y="123.6">P2.6/PCAP1.0/RI1/TRACEPKT1</text>
<text x="133.4" y="124.8">P2.7/RD2/RTS1/TRACEPKT2</text>
<text x="133.6" y="126">P2.8/TD2/TXD2/TRACEPKT3</text>
<text x="149" y="120.4">99</text>
<text x="149" y="121.6">97</text>
<text x="149" y="122.8">96</text>
<text x="149" y="124">95</text>
<text x="149" y="125.2">93</text>
<text x="183.6" y="124.6">8</text>
<text x="183.6" y="123.4">7</text>
<text x="183.6" y="122.2">6</text>
<text x="183.6" y="121">5</text>
<text x="183.6" y="125.8">9</text>
<text x="186.2" y="125.2">GND1</text>
<text x="186.2" y="124">VDDIO1</text>
<text x="186.2" y="122.7">RXD0/PHYAD4</text>
<text x="186.2" y="121.5">RXD1/PHYAD3</text>
<text x="186.2" y="120.3">RXD2/PHYAD2</text>
<text x="201" y="125.4">LED3/NWAYEN</text>
<text x="204.7" y="123">VDDRX</text>
<text x="206.3" y="120.5">RX+</text>
<text x="206.3" y="124.2">PD#</text>
<text x="206.5" y="121.7">RX-</text>
<text x="210.4" y="121">32</text>
<text x="210.4" y="122.2">31</text>
<text x="210.4" y="125.8">28</text>
<text x="210.4" y="124.6">29</text>
<text x="210.4" y="123.4">30</text>
<text x="53.7" y="127">17</text>
<text x="53.7" y="128.2">19</text>
<text x="53.7" y="129.4">21</text>
<text x="53.7" y="130.6">23</text>
<text x="53.7" y="131.8">25</text>
<text x="57.7" y="127.2">18</text>
<text x="57.7" y="128.4">20</text>
<text x="57.7" y="129.6">22</text>
<text x="57.7" y="130.9">24</text>
<text x="107.1" y="128.9">52</text>
<text x="107.1" y="127.7">55</text>
<text x="107.1" y="126.5">58</text>
<text x="110.3" y="129.4">P4.0/A0</text>
<text x="110.3" y="128.2">P4.1/A1</text>
<text x="110.3" y="127">P4.2/A2</text>
<text x="130.3" y="129.6">P2.11/#EINT1/MCIDAT1/I2STX_CLK</text>
<text x="130.6" y="130.9">P2.12/#EINT2/MCIDAT2/I2STX_WS</text>
<text x="131.5" y="127.2">P2.9/U1CONNECT/RXD2/EXTIN0</text>
<text x="140.6" y="128.4">P2.10/#EINT0</text>
<text x="149" y="126.5">92</text>
<text x="149" y="127.7">76</text>
<text x="149" y="128.9">75</text>
<text x="149" y="130.1">73</text>
<text x="149" y="131.3">71</text>
<text x="183" y="129.5">12</text>
<text x="183" y="127.1">10</text>
<text x="183" y="128.3">11</text>
<text x="186.2" y="130">GND2</text>
<text x="186.2" y="127.6">RXC</text>
<text x="186.2" y="126.4">RXDV/CRSDV/PCS_LPBK</text>
<text x="186.2" y="128.8">RXER/ISO</text>
<text x="198.7" y="127.8">LED1/SPD100/NFEF</text>
<text x="201.4" y="126.6">LED2/DUPLEX</text>
<text x="202.4" y="130.2">INT/PHYAD0</text>
<text x="202.9" y="129">LED0/TEST</text>
<text x="210.4" y="129.5">25</text>
<text x="210.4" y="128.3">26</text>
<text x="210.4" y="127.1">27</text>
<text x="53.7" y="133.1">27</text>
<text x="53.7" y="134.3">29</text>
<text x="53.7" y="135.5">31</text>
<text x="53.7" y="136.7">33</text>
<text x="53.7" y="137.9">35</text>
<text x="57.7" y="132.1">26</text>
<text x="57.7" y="133.3">28</text>
<text x="57.7" y="134.5">30</text>
<text x="57.7" y="135.7">32</text>
<text x="57.7" y="136.9">34</text>
<text x="106.5" y="137.4">117</text>
<text x="106.5" y="136.2">119</text>
<text x="106.5" y="135">139</text>
<text x="110.3" y="137.9">VSS-7</text>
<text x="110.3" y="136.7">VSS-8</text>
<text x="110.3" y="135.5">VSS-9</text>
<text x="130.2" y="132.1">P2.13/#EINT3/MCIDAT3/I2STX_SDA</text>
<text x="143.2" y="134.5">P3.0/D0</text>
<text x="143.2" y="135.7">P3.1/D1</text>
<text x="143.2" y="136.9">P3.2/D2</text>
<text x="149" y="133.7">137</text>
<text x="149" y="135">140</text>
<text x="149" y="136.2">144</text>
<text x="149" y="137.4">2</text>
<text x="190.3" y="135.8" transform="rotate(-90 190.3 135.8)">VDDC</text>
<text x="191.5" y="135.8" transform="rotate(-90 191.5 135.8)">TXER</text>
<text x="192.8" y="135.8" transform="rotate(-90 192.8 135.8)">TXC/REFCLK</text>
<text x="194" y="135.8" transform="rotate(-90 194 135.8)">TXEN</text>
<text x="195.2" y="135.8" transform="rotate(-90 195.2 135.8)">TXD0</text>
<text x="196.4" y="135.8" transform="rotate(-90 196.4 135.8)">TXD1</text>
<text x="197.6" y="135.8" transform="rotate(-90 197.6 135.8)">TXD2</text>
<text x="198.8" y="135.8" transform="rotate(-90 198.8 135.8)">TXD3</text>
<text x="200" y="135.8" transform="rotate(-90 200 135.8)">COL/RMII</text>
<text x="201.3" y="135.8" transform="rotate(-90 201.3 135.8)">CRS/RMII_BTB</text>
<text x="202.5" y="135.8" transform="rotate(-90 202.5 135.8)">GND3</text>
<text x="203.7" y="135.8" transform="rotate(-90 203.7 135.8)">VDDIO2</text>
<text x="53.7" y="139.1">37</text>
<text x="54.2" y="143.7" transform="rotate(-90 54.2 143.7)">GND1</text>
<text x="55.4" y="143.7" transform="rotate(-90 55.4 143.7)">GND2</text>
<text x="56.6" y="143.7" transform="rotate(-90 56.6 143.7)">GND3</text>
<text x="57.7" y="138.2">36</text>
<text x="57.7" y="139.4">38</text>
<text x="57.8" y="143.7" transform="rotate(-90 57.8 143.7)">GND4</text>
<text x="59.1" y="143.7" transform="rotate(-90 59.1 143.7)">GND5</text>
<text x="106.5" y="138.6">103</text>
<text x="107.1" y="143.5">44</text>
<text x="107.1" y="142.2">59</text>
<text x="107.1" y="141">65</text>
<text x="107.1" y="139.8">79</text>
<text x="110.3" y="144">VSS-2</text>
<text x="110.3" y="142.8">VSS-3</text>
<text x="110.3" y="141.6">VSS-4</text>
<text x="110.3" y="140.4">VSS-5</text>
<text x="110.3" y="139.1">VSS-6</text>
<text x="143.2" y="138.2">P3.3/D3</text>
<text x="143.2" y="139.4">P3.4/D4</text>
<text x="143.2" y="140.6">P3.5/D5</text>
<text x="143.2" y="141.8">P3.6/D6</text>
<text x="143.2" y="143">P3.7/D7</text>
<text x="149" y="138.6">9</text>
<text x="149" y="139.8">12</text>
<text x="149" y="141">16</text>
<text x="149" y="142.2">19</text>
<text x="149" y="143.5">45</text>
<text x="189.8" y="139" transform="rotate(-90 189.8 139)">13</text>
<text x="191" y="139" transform="rotate(-90 191 139)">14</text>
<text x="192.2" y="139" transform="rotate(-90 192.2 139)">15</text>
<text x="193.4" y="139" transform="rotate(-90 193.4 139)">16</text>
<text x="194.6" y="139" transform="rotate(-90 194.6 139)">17</text>
<text x="195.9" y="139" transform="rotate(-90 195.9 139)">18</text>
<text x="197.1" y="139" transform="rotate(-90 197.1 139)">19</text>
<text x="198.3" y="139" transform="rotate(-90 198.3 139)">20</text>
<text x="199.5" y="139" transform="rotate(-90 199.5 139)">21</text>
<text x="200.7" y="139" transform="rotate(-90 200.7 139)">22</text>
<text x="201.9" y="139" transform="rotate(-90 201.9 139)">23</text>
<text x="203.2" y="139" transform="rotate(-90 203.2 139)">24</text>
<text x="237.4" y="142.2">1</text>
<text x="240.4" y="142.2">2</text>
<text x="255.3" y="142.9">2</text>
<text x="255.3" y="141.6">3</text>
<text x="62.4" y="145.9">1</text>
<text x="62.4" y="144.7">2</text>
<text x="107.1" y="144.7">22</text>
<text x="107.1" y="147.1">15</text>
<text x="110.3" y="145.2">VSS-1</text>
<text x="110.3" y="147.6">VSSA</text>
<text x="136" y="144.2">P3.23/CAP0.0/PCAP1.0</text>
<text x="136.2" y="145.4">P3.24/CAP0.1/PWM1.1</text>
<text x="136.2" y="146.6">P3.25/MAT0.0/PWM1.2</text>
<text x="136.2" y="147.9">P3.26/MAT0.1/PWM1.3</text>
<text x="149" y="144.7">40</text>
<text x="149" y="145.9">39</text>
<text x="149" y="147.1">38</text>
<text x="233.7" y="148.9">4</text>
<text x="233.7" y="145.3">1</text>
<text x="233.7" y="147.7">3</text>
<text x="233.7" y="146.5">2</text>
<text x="235.4" y="149.5">RXD</text>
<text x="235.4" y="145.8">TXD</text>
<text x="235.4" y="148.3">VDD</text>
<text x="235.4" y="147">VSS</text>
<text x="238.8" y="147.3">CANH</text>
<text x="239" y="148.5">CANL</text>
<text x="239" y="149.7">VREF</text>
<text x="240.3" y="146.1">RS</text>
<text x="242.8" y="146.5">7</text>
<text x="242.8" y="147.7">6</text>
<text x="242.8" y="145.3">8</text>
<text x="242.8" y="148.9">5</text>
<text x="251.2" y="147.2" transform="rotate(-90 251.2 147.2)">1</text>
<text x="251.2" y="144.3" transform="rotate(-90 251.2 144.3)">2</text>
<text x="255.3" y="144.1">1</text>
</g>
<g font-size="1" fill="#800000">
<text x="182.2" y="83.8">E/D</text>
<text x="181.8" y="89.3">OUT</text>
<text x="186.3" y="84.4">VDD</text>
<text x="186.4" y="89.3">VSS</text>
</g>
<g font-size=".9" fill="#808080">
<text x="234" y="35.8">+5V_USB</text>
<text x="143.3" y="41.6">LPC2378</text>
<text x="145.7" y="40.3">U1</text>
<text x="234" y="38.2">+5V_EXT</text>
<text x="234" y="37">+5V_JLINK</text>
<text x="236.7" y="40.9">5-6 - +5V_USB</text>
<text x="65.7" y="46.7">SD/MMC</text>
<text x="169.6" y="46.1">TXD0</text>
<text x="236.7" y="43.4">1-2 - +5V_EXT</text>
<text x="236.7" y="42.1">3-4 - +5V_JLINK</text>
<text x="169.6" y="49.7">RXD0</text>
<text x="65.4" y="67.7">SD-CARD</text>
<text x="99.4" y="87.4">NA</text>
<text x="257.7" y="95.3">TXD2</text>
<text x="52.3" y="99">+5V_JLINK</text>
<text x="257.7" y="100.2">MISO</text>
<text x="257.7" y="101.4">MOSI</text>
<text x="257.7" y="96.5">RXD2</text>
<text x="257.7" y="97.7">SCL0</text>
<text x="257.7" y="99">SDA0</text>
<text x="100.6" y="105.6">IR_RX</text>
<text x="100.6" y="106.9">IR_TX</text>
<text x="257.7" y="102.6">SCK</text>
<text x="257.7" y="103.8">SSEL</text>
<text x="248.6" y="112.3">GREEN</text>
<text x="252.4" y="108.6">75</text>
<text x="254.8" y="108.6">75</text>
<text x="248.6" y="114.5">YELLOW</text>
<text x="249.2" y="119.6">1nF/2kV</text>
<text x="252.4" y="115.9">75</text>
<text x="254.8" y="115.9">75</text>
<text x="192.1" y="144.3" transform="rotate(-90 192.1 144.3)">E_RX_CLK</text>
<text x="193.2" y="144.1" transform="rotate(-90 193.2 144.1)">E_TX_EN</text>
<text x="194.5" y="144.1" transform="rotate(-90 194.5 144.1)">E_TXD0</text>
<text x="195.7" y="144.1" transform="rotate(-90 195.7 144.1)">E_TXD1</text>
</g>
<g font-size=".9" fill="#800000">
<text x="220.1" y="43.2" transform="rotate(-90 220.1 43.2)">+</text>
<text x="235.2" y="45.6" transform="rotate(-90 235.2 45.6)">+</text>
<text x="246.8" y="45.6" transform="rotate(-90 246.8 45.6)">+</text>
<text x="263.8" y="45.6" transform="rotate(-90 263.8 45.6)">+</text>
<text x="93.1" y="56.5" transform="rotate(-90 93.1 56.5)">+</text>
<text x="42" y="66.3" transform="rotate(-90 42 66.3)">+</text>
<text x="202.2" y="100">+</text>
<text x="183.4" y="105.9" transform="rotate(-90 183.4 105.9)">+</text>
<text x="245.5" y="107.3">1:1</text>
<text x="245.5" y="115.8">1:1</text>
<text x="185.2" y="146.6" transform="rotate(-90 185.2 146.6)">+</text>
</g>
<g font-size=".7" fill="#808080">
<text x="189.8" y="54.4">VCC</text>
<text x="193.3" y="54.4">GND</text>
</g>
<text font-size=".4" fill="#800000" x="103.7" y="72.4">GND</text>
</g></defs>
<g fill="none" stroke="#800000" stroke-width=".13">
<path d="M83.6 57.3h1.7M86.8 57.3h1.7M97 42.1v1.7M97 45.4v1.6M100.6 42.1v1.7M100.6 45.4v1.6M101.9 56.7l.6 .6-.6 .7-.7-.7zM102.5 57.3h1.2M79.4 67.1h1.2M81.8 67.1h1.2M196.5 87.7h1M196.5 87.5v.5"/>
<path d="M197.6 86.9v1.7M198.5 84.7v1.9M198.5 88.8v2M208.8 96.5l.6-.9 .6 .9M209.4 95.6v1.2M212.3 87.7h1.1M212.3 87.5v.5M213.4 86.9v1.7M214.3 84.7v1.9M214.3 88.8v2M222.2 96.5l.6-.9 .6 .9M222.8 95.6v1.2"/>
<path d="M227 96.5l.6-.9 .6 .9M227.6 95.6v1.2M235.5 96.5l.6-.9 .6 .9M236.1 95.6v1.2"/>
<circle cx="101.8" cy="57.3" r=".29"/>
<circle cx="198.5" cy="86.9" r=".23"/>
<circle cx="198.5" cy="88.6" r=".23"/>
<circle cx="214.2" cy="86.9" r=".23"/>
<circle cx="214.2" cy="88.6" r=".23"/>
</g>
<g fill="#800000" stroke="#800000" stroke-width=".13">
<path d="M100.2 44a.6 .6 0 0 1 .6-.2 .6 .6 0 0 1 .4 .6h-1.2z" fill-rule="evenodd"/>
<path d="M100 44.7h1.2a.59 .59 0 0 1-.6 .6 .59 .59 0 0 1-.6-.6z" fill-rule="evenodd"/>
<path d="M86.2 56.7a.6 .6 0 0 1 .6 .6 .6 .6 0 0 1-.6 .6z" fill-rule="evenodd"/>
<path d="M85.4 56.9l.4-.2v1.2a.61 .61 0 0 1-.5-.3 .61 .61 0 0 1 .1-.7z" fill-rule="evenodd"/>
<path d="M96.6 44a.6 .6 0 0 1 .6-.2 .6 .6 0 0 1 .4 .6h-1.2z" fill-rule="evenodd"/>
<path d="M96.4 44.7h1.2a.59 .59 0 0 1-.6 .6 .59 .59 0 0 1-.6-.6z" fill-rule="evenodd"/>
</g>
<path d="M81.3 66.1h.2v1.9h-.2z" fill="#800000"/>
<path d="M81.3 66.1h.2v1.9h-.2z" fill="none" stroke="#800000" stroke-width=".13"/>
<path d="M80.9 66.1h.1v1.9h-.1z" fill="#800000"/>
<path d="M80.6 67.1h.2M80.8 66.1h.2v1.9h-.2zM81.6 67.1h.2M82.4 65.8h1.2M84.8 65.8h1.2" fill="none" stroke="#800000" stroke-width=".13"/>
<path d="M84.4 64.9h.2v1.9h-.2z" fill="#800000"/>
<path d="M84.3 64.9h.3v1.9h-.3z" fill="none" stroke="#800000" stroke-width=".13"/>
<path d="M83.9 64.9h.2v1.9h-.2z" fill="#800000"/>
<path d="M83.6 65.8h.3M83.9 64.9h.2v1.9h-.2zM84.6 65.8h.2M85.4 64.6h1.3M87.9 64.6h1.2" fill="none" stroke="#800000" stroke-width=".13"/>
<path d="M87.4 63.7h.2v1.9h-.2z" fill="#800000"/>
<path d="M87.4 63.7h.2v1.9h-.2z" fill="none" stroke="#800000" stroke-width=".13"/>
<path d="M86.9 63.7h.2v1.9h-.2z" fill="#800000"/>
<path d="M79.4 63.4h1.2M81.8 63.4h1.2M86.7 64.6h.2M86.9 63.7h.2v1.9h-.2zM87.6 64.6h.3" fill="none" stroke="#800000" stroke-width=".13"/>
<path d="M81.3 62.5h.2v1.9h-.2z" fill="#800000"/>
<path d="M81.3 62.4h.2v2h-.2z" fill="none" stroke="#800000" stroke-width=".13"/>
<path d="M80.9 62.5h.1v1.9h-.1z" fill="#800000"/>
<path d="M80.6 63.4h.2M80.8 62.4h.2v2h-.2zM81.6 63.4h.2M82.4 62.2h1.2M84.8 62.2h1.2" fill="none" stroke="#800000" stroke-width=".13"/>
<path d="M84.4 61.3h.2v1.9h-.2z" fill="#800000"/>
<path d="M84.3 61.2h.3v2h-.3z" fill="none" stroke="#800000" stroke-width=".13"/>
<path d="M83.9 61.3h.2v1.9h-.2z" fill="#800000"/>
<path d="M83.6 62.2h.3M83.9 61.2h.2v2h-.2zM84.6 62.2h.2M85.4 61h1.3M87.9 61h1.2" fill="none" stroke="#800000" stroke-width=".13"/>
<path d="M87.4 60h.2v1.9h-.2z" fill="#800000"/>
<path d="M87.4 60h.2v1.9h-.2z" fill="none" stroke="#800000" stroke-width=".13"/>
<path d="M86.9 60h.2v1.9h-.2z" fill="#800000"/>
<path d="M81.2 51.3h1.2M83.6 51.3h1.2M86.7 61h.2M86.9 60h.2v1.9h-.2zM87.6 61h.3" fill="none" stroke="#800000" stroke-width=".13"/>
<path d="M83.2 50.3h.2v1.9h-.2z" fill="#800000"/>
<path d="M83.1 50.3h.3v1.9h-.3z" fill="none" stroke="#800000" stroke-width=".13"/>
<path d="M82.7 50.3h.2v1.9h-.2z" fill="#800000"/>
<path d="M82.4 51.3h.3M82.7 50.3h.2v1.9h-.2zM83.4 51.3h.2M84.8 53.7h1.2M87.3 53.7h1.2" fill="none" stroke="#800000" stroke-width=".13"/>
<path d="M86.8 52.7h.2v2h-.2z" fill="#800000"/>
<path d="M86.8 52.7h.2v2h-.2z" fill="none" stroke="#800000" stroke-width=".13"/>
<path d="M86.3 52.7h.2v2h-.2z" fill="#800000"/>
<path d="M86 53.7h.3M86.3 52.7h.2v2h-.2zM87 53.7h.3M87.3 52.5h1.2M89.7 52.5h1.2" fill="none" stroke="#800000" stroke-width=".13"/>
<path d="M89.2 51.5h.2v1.9h-.2z" fill="#800000"/>
<path d="M89.2 51.5h.2v1.9h-.2z" fill="none" stroke="#800000" stroke-width=".13"/>
<path d="M88.7 51.5h.2v1.9h-.2z" fill="#800000"/>
<path d="M83.6 50h1.2M86 50h1.3M88.5 52.5h.2M88.7 51.5h.2v1.9h-.2zM89.4 52.5h.3" fill="none" stroke="#800000" stroke-width=".13"/>
<path d="M85.6 49.1h.2v1.9h-.2z" fill="#800000"/>
<path d="M85.6 49.1h.2v1.9h-.2z" fill="none" stroke="#800000" stroke-width=".13"/>
<path d="M85.1 49.1h.2v1.9h-.2z" fill="#800000"/>
<path d="M84.8 50h.3M85.1 49.1h.2v1.9h-.2zM85.8 50h.2M87.3 48.8h1.2M89.7 48.8h1.2" fill="none" stroke="#800000" stroke-width=".13"/>
<path d="M89.2 47.9h.2v1.9h-.2z" fill="#800000"/>
<path d="M89.2 47.9h.2v1.9h-.2z" fill="none" stroke="#800000" stroke-width=".13"/>
<path d="M88.7 47.9h.2v1.9h-.2z" fill="#800000"/>
<path d="M88.5 48.8h.2M88.7 47.9h.2v1.9h-.2zM89.4 48.8h.3M95.8 76.8h1.2M98.2 76.8h1.2" fill="none" stroke="#800000" stroke-width=".13"/>
<path d="M97.7 75.8h.2v1.9h-.2z" fill="#800000"/>
<path d="M97.7 75.8h.2v1.9h-.2z" fill="none" stroke="#800000" stroke-width=".13"/>
<path d="M97.3 75.8h.1v1.9h-.1z" fill="#800000"/>
<path d="M97 76.8h.2M97.2 75.8h.2v1.9h-.2zM98 76.8h.2M95.8 80.4h1.2M98.2 80.4h1.2" fill="none" stroke="#800000" stroke-width=".13"/>
<path d="M97.7 79.5h.2v1.9h-.2z" fill="#800000"/>
<path d="M97.7 79.5h.2v1.9h-.2z" fill="none" stroke="#800000" stroke-width=".13"/>
<path d="M97.3 79.5h.1v1.9h-.1z" fill="#800000"/>
<path d="M95.8 70.7h1.2M97.2 79.5h.2v1.9h-.2zM98.2 70.7h1.2M97 80.4h.2M98 80.4h.2" fill="none" stroke="#800000" stroke-width=".13"/>
<path d="M97.7 69.8h.2v1.9h-.2z" fill="#800000"/>
<path d="M97.7 69.7h.2v2h-.2z" fill="none" stroke="#800000" stroke-width=".13"/>
<path d="M97.3 69.8h.1v1.9h-.1z" fill="#800000"/>
<path d="M95.8 74.4h1.2M97 70.7h.2M97.2 69.7h.2v2h-.2zM98 70.7h.2M98.2 74.4h1.2" fill="none" stroke="#800000" stroke-width=".13"/>
<path d="M97.7 73.4h.2v1.9h-.2z" fill="#800000"/>
<path d="M97.7 73.4h.2v1.9h-.2z" fill="none" stroke="#800000" stroke-width=".13"/>
<path d="M97.3 73.4h.1v1.9h-.1z" fill="#800000"/>
<path d="M193 36.7h1.2M195.4 36.7h1.2M97 74.4h.2M97.2 73.4h.2v1.9h-.2zM98 74.4h.2" fill="none" stroke="#800000" stroke-width=".13"/>
<path d="M194.5 35.7h.2v1.9h-.2z" fill="#800000"/>
<path d="M194.5 35.7h.2v1.9h-.2z" fill="none" stroke="#800000" stroke-width=".13"/>
<path d="M195 35.7h.2v1.9h-.2z" fill="#800000"/>
<path d="M193 39.1h1.2M194.2 36.7h.3M194.9 35.7h.3v1.9h-.3zM195.2 36.7h.2M195.4 39.1h1.2" fill="none" stroke="#800000" stroke-width=".13"/>
<path d="M194.5 38.2h.2v1.9h-.2z" fill="#800000"/>
<path d="M194.5 38.1h.2v2h-.2z" fill="none" stroke="#800000" stroke-width=".13"/>
<path d="M195 38.2h.2v1.9h-.2z" fill="#800000"/>
<path d="M168.7 35.5h1.2M171.1 35.5h1.2M194.2 39.1h.3M194.9 38.1h.3v2h-.3zM195.2 39.1h.2" fill="none" stroke="#800000" stroke-width=".13"/>
<path d="M170.2 34.5h.2v1.9h-.2z" fill="#800000"/>
<path d="M170.2 34.5h.2v1.9h-.2z" fill="none" stroke="#800000" stroke-width=".13"/>
<path d="M170.7 34.5h.2v1.9h-.2z" fill="#800000"/>
<path d="M169.9 35.5h.3M170.6 34.5h.3v1.9h-.3zM170.9 35.5h.2M168.7 40.3h1.2M171.1 40.3h1.2" fill="none" stroke="#800000" stroke-width=".13"/>
<path d="M170.2 39.4h.2v1.9h-.2z" fill="#800000"/>
<path d="M170.2 39.3h.2v2h-.2z" fill="none" stroke="#800000" stroke-width=".13"/>
<path d="M170.7 39.4h.2v1.9h-.2z" fill="#800000"/>
<path d="M170.6 39.3h.3v2h-.3zM169.9 40.3h.3M170.9 40.3h.2M189.4 65.8v1.3M189.4 68.3v1.2" fill="none" stroke="#800000" stroke-width=".13"/>
<path d="M188.4 67.3h1.9v.2h-1.9z" fill="#800000"/>
<path d="M188.4 67.3h1.9v.2h-1.9z" fill="none" stroke="#800000" stroke-width=".13"/>
<path d="M188.4 67.8h1.9v.2h-1.9z" fill="#800000"/>
<path d="M188.4 67.8h1.9v.2h-1.9zM189.4 67.1v.2M189.4 68v.3M200.9 86.5v1.2M200.9 88.9v1.2" fill="none" stroke="#800000" stroke-width=".13"/>
<path d="M199.9 88h1.9v.2h-1.9z" fill="#800000"/>
<path d="M199.9 88h1.9v.2h-1.9z" fill="none" stroke="#800000" stroke-width=".13"/>
<path d="M199.9 88.5h1.9v.2h-1.9z" fill="#800000"/>
<path d="M97 55.5v1.2M97 58v1.2M199.9 88.5h1.9v.2h-1.9zM200.9 87.7v.3M200.9 88.7v.2" fill="none" stroke="#800000" stroke-width=".13"/>
<path d="M96 57h1.9v.2h-1.9z" fill="#800000"/>
<path d="M96 57h1.9v.2h-1.9z" fill="none" stroke="#800000" stroke-width=".13"/>
<path d="M96 57.5h1.9v.2h-1.9z" fill="#800000"/>
<path d="M93.3 55.5v1.2M93.3 58v1.2M96 57.5h1.9v.2h-1.9zM97 56.7v.3M97 57.7v.3" fill="none" stroke="#800000" stroke-width=".13"/>
<path d="M92.6 57.6h1.5v.3h-1.5z" fill="#800000"/>
<path d="M37.4 36.7h1.2M39.9 36.7h1.2M92.6 57.5h1.5v.4h-1.5zM92.6 56.7h1.5v.4h-1.5z" fill="none" stroke="#800000" stroke-width=".13"/>
<path d="M38.9 35.7h.2v1.9h-.2z" fill="#800000"/>
<path d="M38.9 35.7h.2v1.9h-.2z" fill="none" stroke="#800000" stroke-width=".13"/>
<path d="M39.4 35.7h.2v1.9h-.2z" fill="#800000"/>
<path d="M38.6 36.7h.3M39.4 35.7h.2v1.9h-.2zM39.6 36.7h.3M42.3 65.2v1.3M42.3 67.7v1.2" fill="none" stroke="#800000" stroke-width=".13"/>
<path d="M41.5 67.3h1.6v.3h-1.6z" fill="#800000"/>
<path d="M264.1 44.6v1.2M264.1 47v1.2M41.5 67.2h1.6v.4h-1.6zM41.6 66.5h1.4v.4h-1.4z" fill="none" stroke="#800000" stroke-width=".13"/>
<path d="M263.3 46.6h1.6v.4h-1.6z" fill="#800000"/>
<path d="M233.1 44.6v1.2M233.1 47v1.2M263.3 46.6h1.6v.4h-1.6zM263.4 45.8h1.4v.4h-1.4z" fill="none" stroke="#800000" stroke-width=".13"/>
<path d="M232.2 46.5h1.9v.2h-1.9z" fill="#800000"/>
<path d="M232.1 46.5h2v.2h-2z" fill="none" stroke="#800000" stroke-width=".13"/>
<path d="M232.2 46.1h1.9v.1h-1.9z" fill="#800000"/>
<path d="M232.1 46h2v.2h-2zM233.1 45.8v.2M233.1 46.8v.2M261 44.6v1.2M261 47v1.2" fill="none" stroke="#800000" stroke-width=".13"/>
<path d="M260.1 46.5h1.9v.2h-1.9z" fill="#800000"/>
<path d="M260.1 46.5h1.9v.2h-1.9z" fill="none" stroke="#800000" stroke-width=".13"/>
<path d="M260.1 46.1h1.9v.1h-1.9z" fill="#800000"/>
<path d="M260.1 46h1.9v.2h-1.9zM261 45.8v.2M261 46.8v.2M237.4 87.1v1.2M237.4 89.6v1.2" fill="none" stroke="#800000" stroke-width=".13"/>
<path d="M236.4 89.1h1.9v.2h-1.9z" fill="#800000"/>
<path d="M236.4 89.1h1.9v.2h-1.9z" fill="none" stroke="#800000" stroke-width=".13"/>
<path d="M236.4 88.6h1.9v.2h-1.9z" fill="#800000"/>
<path d="M236.4 88.6h1.9v.2h-1.9zM237.4 88.3v.3M237.4 89.3v.3M242.2 87.1v1.2M242.2 89.6v1.2" fill="none" stroke="#800000" stroke-width=".13"/>
<path d="M241.3 89.1h1.9v.2h-1.9z" fill="#800000"/>
<path d="M241.2 89.1h2v.2h-2z" fill="none" stroke="#800000" stroke-width=".13"/>
<path d="M241.3 88.6h1.9v.2h-1.9z" fill="#800000"/>
<path d="M36.2 62.8v1.2M36.2 65.2v1.3M241.2 88.6h2v.2h-2zM242.2 88.3v.3M242.2 89.3v.3" fill="none" stroke="#800000" stroke-width=".13"/>
<path d="M35.3 64.3h1.9v.2h-1.9z" fill="#800000"/>
<path d="M35.2 64.3h2v.2h-2z" fill="none" stroke="#800000" stroke-width=".13"/>
<path d="M35.3 64.8h1.9v.2h-1.9z" fill="#800000"/>
<path d="M190.6 57.3h1.2M193 57.3h1.2M35.2 64.7h2v.3h-2zM36.2 64v.3M36.2 65v.2" fill="none" stroke="#800000" stroke-width=".13"/>
<path d="M192 56.4h.3v1.9h-.3z" fill="#800000"/>
<path d="M192 56.4h.3v1.9h-.3z" fill="none" stroke="#800000" stroke-width=".13"/>
<path d="M192.5 56.4h.2v1.9h-.2z" fill="#800000"/>
<path d="M191.8 57.3h.2M192.5 56.4h.2v1.9h-.2zM192.8 57.3h.2M235.5 44.6v1.2M235.5 47v1.2" fill="none" stroke="#800000" stroke-width=".13"/>
<path d="M234.8 46.6h1.5v.4h-1.5z" fill="#800000"/>
<path d="M220.3 42.1v1.3M220.3 44.6v1.2M234.7 46.6h1.6v.4h-1.6zM234.8 45.8h1.5v.4h-1.5z" fill="none" stroke="#800000" stroke-width=".13"/>
<path d="M219.6 44.2h1.5v.4h-1.5z" fill="#800000"/>
<path d="M219.6 44.2h1.5v.4h-1.5zM219.6 43.4h1.5v.4h-1.5zM247.1 44.6v1.2M247.1 47v1.2" fill="none" stroke="#800000" stroke-width=".13"/>
<path d="M246.3 46.6h1.5v.4h-1.5z" fill="#800000"/>
<path d="M246.3 46.6h1.5v.4h-1.5zM246.4 45.8h1.4v.4h-1.4zM216.7 86.5v1.2M216.7 88.9v1.2" fill="none" stroke="#800000" stroke-width=".13"/>
<path d="M215.7 88h2v.2h-2z" fill="#800000"/>
<path d="M215.7 88h2v.2h-2z" fill="none" stroke="#800000" stroke-width=".13"/>
<path d="M215.7 88.5h2v.2h-2z" fill="#800000"/>
<path d="M215.7 88.5h2v.2h-2zM216.7 87.7v.3M216.7 88.7v.2M230.7 141.2v1.2M230.7 143.6v1.2" fill="none" stroke="#800000" stroke-width=".13"/>
<path d="M229.7 143.2h1.9v.2h-1.9z" fill="#800000"/>
<path d="M229.7 143.2h1.9v.2h-1.9z" fill="none" stroke="#800000" stroke-width=".13"/>
<path d="M229.7 142.7h1.9v.2h-1.9z" fill="#800000"/>
<path d="M179 132.7v1.2M179 135.1v1.2M229.7 142.7h1.9v.2h-1.9zM230.7 142.4v.3M230.7 143.4v.2" fill="none" stroke="#800000" stroke-width=".13"/>
<path d="M178.1 134.2h1.9v.2h-1.9z" fill="#800000"/>
<path d="M178.1 134.2h1.9v.2h-1.9z" fill="none" stroke="#800000" stroke-width=".13"/>
<path d="M178.1 134.7h1.9v.2h-1.9z" fill="#800000"/>
<path d="M178.1 134.6h1.9v.3h-1.9zM179 133.9v.3M179 134.9v.2M182.1 144.3h1.2M184.5 144.3h1.2" fill="none" stroke="#800000" stroke-width=".13"/>
<path d="M183.5 143.3h.2v1.9h-.2z" fill="#800000"/>
<path d="M183.5 143.3h.2v1.9h-.2z" fill="none" stroke="#800000" stroke-width=".13"/>
<path d="M184 143.3h.2v1.9h-.2z" fill="#800000"/>
<path d="M182.1 146.7h1.2M183.3 144.3h.2M184 143.3h.2v1.9h-.2zM184.3 144.3h.2M184.5 146.7h1.2" fill="none" stroke="#800000" stroke-width=".13"/>
<path d="M183.3 145.9h.4v1.5h-.4z" fill="#800000"/>
<path d="M183.3 145.9h.4v1.5h-.4zM184.1 145.9h.4v1.5h-.4zM211.2 142.4v1.2M211.2 144.8v1.3" fill="none" stroke="#800000" stroke-width=".13"/>
<path d="M210.3 143.9h1.9v.2h-1.9z" fill="#800000"/>
<path d="M210.2 143.9h2v.2h-2z" fill="none" stroke="#800000" stroke-width=".13"/>
<path d="M210.3 144.4h1.9v.2h-1.9z" fill="#800000"/>
<path d="M222.8 122.4v1.2M222.8 124.8v1.2M210.2 144.4h2v.2h-2zM211.2 143.6v.3M211.2 144.6v.2" fill="none" stroke="#800000" stroke-width=".13"/>
<path d="M221.8 123.8h1.9v.2h-1.9z" fill="#800000"/>
<path d="M221.8 123.8h1.9v.2h-1.9z" fill="none" stroke="#800000" stroke-width=".13"/>
<path d="M221.8 124.3h1.9v.2h-1.9z" fill="#800000"/>
<path d="M221.8 124.3h1.9v.2h-1.9zM222.8 123.6v.2M222.8 124.5v.3M230.1 123v1.2M230.1 125.4v1.2" fill="none" stroke="#800000" stroke-width=".13"/>
<path d="M229.1 124.9h1.9v.2h-1.9z" fill="#800000"/>
<path d="M229.1 124.9h1.9v.2h-1.9z" fill="none" stroke="#800000" stroke-width=".13"/>
<path d="M229.1 124.5h1.9v.2h-1.9z" fill="#800000"/>
<path d="M244 98.7v1.2M244 101.1v1.2M229.1 124.4h1.9v.3h-1.9zM230.1 124.2v.2M230.1 125.2v.2" fill="none" stroke="#800000" stroke-width=".13"/>
<path d="M243.1 100.1h1.9v.3h-1.9z" fill="#800000"/>
<path d="M243.1 100.1h1.9v.3h-1.9z" fill="none" stroke="#800000" stroke-width=".13"/>
<path d="M243.1 100.6h1.9v.2h-1.9z" fill="#800000"/>
<path d="M202.1 96.8v1.3M202.1 99.3v1.2M244 99.9v.2M243.1 100.6h1.9v.2h-1.9zM244 100.9v.2" fill="none" stroke="#800000" stroke-width=".13"/>
<path d="M201.3 98.1h1.6v.4h-1.6z" fill="#800000"/>
<path d="M197.2 96.8v1.3M197.2 99.3v1.2M201.3 98.1h1.6v.4h-1.6zM201.4 98.8h1.4v.5h-1.4z" fill="none" stroke="#800000" stroke-width=".13"/>
<path d="M196.3 98.3h1.9v.2h-1.9z" fill="#800000"/>
<path d="M196.3 98.3h1.9v.2h-1.9z" fill="none" stroke="#800000" stroke-width=".13"/>
<path d="M196.3 98.8h1.9v.2h-1.9z" fill="#800000"/>
<path d="M196.3 98.8h1.9v.2h-1.9zM197.2 98.1v.2M197.2 99v.3M180.2 103.5h1.3M182.7 103.5h1.2" fill="none" stroke="#800000" stroke-width=".13"/>
<path d="M182.2 102.6h.2v1.9h-.2z" fill="#800000"/>
<path d="M182.2 102.6h.2v1.9h-.2z" fill="none" stroke="#800000" stroke-width=".13"/>
<path d="M181.7 102.6h.2v1.9h-.2z" fill="#800000"/>
<path d="M180.2 106h1.3M181.5 103.5h.2M181.7 102.6h.2v1.9h-.2zM182.4 103.5h.3M182.7 106h1.2" fill="none" stroke="#800000" stroke-width=".13"/>
<path d="M181.5 105.2h.4v1.5h-.4z" fill="#800000"/>
<g fill="none" stroke="#800000" stroke-width=".13">
<path d="M213 39.7v1.2M214.8 39.8l.8-.8 .2 1zM214.8 37.2l1-.2-.2 1zM215.1 37.6l-.8 .9 .8 .9M215.4 36.6l.8 .8M216.2 39.6l-.8 .8M217.2 37.4l.8-.8 .2 1zM217.2 39.6l1-.2-.2 1zM217.5 36.9l-.8-.8-.9 .9M217.8 39l.9 .9M218.2 37.6l.9 .9-.9 .9M218.7 37.2l-.9 .8"/>
<path d="M36.8 55.5h1.3M40.5 55.5h1.2M46.9 50.7h1.8M47.8 49.4v1.3M59.6 41.6h1.8M60.5 40.3v1.3M63.3 41.6h1.8M64.2 40.3v1.3M93.3 59.2v1.2M97 59.2v1.2M156.5 44h1.3M156.5 45.2h1.3"/>
<path d="M156.5 51.3h1.3M156.5 52.5h1.3M156.5 53.7h1.3M156.5 54.9h1.3M190.3 51.3h1.8M191.2 50v1.3M196.3 59.2h1.9M197.2 58v1.2M199.4 41.6h1.8M200.3 40.3v1.3M203.9 56.7v1.8M205.1 56.7v1.8"/>
<path d="M212.1 40.9h1.9M215.8 40l.9 .9 .8-.8M216.7 46.4l.6 .6-.6 .6-.6-.6zM217.3 47h1.2M219.4 50h1.9M220.3 48.8v1.2M223.7 50h1.8M224.6 48.8v1.2M232.2 50h1.8M233.1 48.8v1.2M234.6 50h1.8M235.5 48.8v1.2"/>
<path d="M246.2 50h1.8M247.1 48.8v1.2M251.6 50h1.9M252.5 48.8v1.2M260.1 50h1.9M261 48.8v1.2M263.2 50h1.8M264.1 48.8v1.2M266.8 50h1.8M267.7 48.8v1.2M28 71.3h1.8M28.9 70.1v1.2"/>
<path d="M32.9 71.3h1.8M33.8 70.1v1.2M35.3 71.3h1.8M36.2 70.1v1.2M41.4 71.3h1.8M42.3 70.1v1.2M46.9 66.5h1.8M47.8 65.2v1.3M59.6 71.3h1.8M60.5 70.1v1.2M76.6 70.7h1.9M77.6 69.5v1.2"/>
<path d="M92.4 60.4h1.9M96.1 60.4h1.8M156.5 71.9h1.3M156.5 73.1h1.3M156.5 74.4h1.3M156.5 75.6h1.3M172 73.1h1.9M172.9 71.9v1.2M176 63.4h4.8M176.6 62.8l1.2 .6-1.2 .6zM177.8 62.8v1.2M178.4 62.2v1.2"/>
<path d="M179 63.4l1.2-.6v1.2zM179 62.8v1.2M188.4 73.1h1.9M189.4 71.9v1.2M190.9 73.1h1.8M191.8 71.9v1.2M199.4 73.1h1.8M199.7 68.9h1.2M200.3 68.9l.6 1.2h-1.2zM200.3 68.3v2.4M200.3 71.9v1.2M203 73.1h1.8"/>
<path d="M203.9 71.9v1.2M251.9 79.8v1.2M43.5 99.3h2.4M43.5 98.1h2.4M43.5 92h2.4M43.5 90.8h2.4M43.5 88.3h2.4M43.5 89.6h2.4M43.5 93.2h2.4M43.5 94.4h2.4M43.5 95.6h2.4M43.5 96.8h2.4"/>
<path d="M48.4 99.3h2.4M48.4 98.1h2.4M48.4 92h2.4M48.4 90.8h2.4M48.4 88.3h2.4M48.4 89.6h2.4M48.4 93.2h2.4M48.4 94.4h2.4M48.4 95.6h2.4M48.4 96.8h2.4M67.8 99.3h1.8M67.8 98.1h1.8"/>
<path d="M93.6 82.3h1.9M94.5 81v1.3M96.4 98.7h1.2M97 84.1h1.2M157.1 97.5h1.3M157.1 99.9h1.3M179 84.1h4.9v1.2M179 86.5h3.1M185.7 85h1.2v1M186.3 87h1.2M186.3 86h1.2M186.4 86.3h1v.4h-1z"/>
<path d="M186.9 87v1h-1.2M188.7 84.1h2.5M188.7 88.9h2.5M191.5 90.8h1.8M192.4 89.6v1.2M197.5 92h1.9M198.5 90.8v1.2M200 92h1.8M200.9 90.8v1.2M213.4 92h1.8M214.3 90.8v1.2M215.8 92h1.8"/>
<path d="M216.7 90.8v1.2M236.4 92h1.9M237.4 90.8v1.2M241.3 82.3h1.8M241.3 92h1.8M242.2 81v1.3M242.2 90.8v1.2M251 81h1.9M254.1 97.5h1.8M254.7 92h1.8M255 96.2v1.3M255.6 90.8v1.2"/>
<path d="M41.4 106.6h1.8M42.3 105.3v1.3M47.8 119.3h1.2M47.8 118.4v1.8M54.1 106.6h1.9M55.1 105.3v1.3M58.4 106.6h1.8M59.3 105.3v1.3M62.1 106.6h1.8M63 105.3v1.3M65.7 106.6h1.8M66.6 105.3v1.3"/>
<path d="M78.8 112.6h1.2M78.8 111.7v1.9M80.3 102.9h1.8M81.2 101.7v1.2M81.8 116.9h1.2M81.8 119.3h1.2M81.8 105.3h1.2M81.8 107.8h1.2M81.8 110.2h1.2M81.8 112.6h1.2M97 106h1.2M97 107.2h1.2"/>
<path d="M105.5 103.5h1.2M105.5 104.7h1.2M105.5 108.4h1.2M105.5 109.6h1.2M105.5 110.8h1.2M105.5 112h1.2M105.5 113.2h1.2M105.5 114.5h1.2M105.5 115.7h1.2M105.5 116.9h1.2M105.5 118.1h1.2M105.5 119.3h1.2"/>
<path d="M157.1 103.5h1.3M157.1 104.7h1.3M157.1 106h1.3M157.1 107.2h1.3M157.1 108.4h1.3M157.1 109.6h1.3M157.1 110.8h1.3M157.1 113.2h1.3M157.1 101.1h1.3M157.1 102.3h1.3M166.9 119.9v1.3M177.5 109.6h1.8"/>
<path d="M178.4 108.4v1.2M181.5 105.2h.4v1.5h-.4zM182.2 105.2h.5v1.5h-.5zM213.4 118.7h1.8M214.3 117.5v1.2M243.1 105.1h1.9M244 103.8v1.3M66.9 127.8h1.8M67.8 126.6v1.2M80 124.2h1.2M80 123.3v1.8M81.8 121.8h1.2"/>
<path d="M81.8 124.2h1.2M84.2 127.8h1.2M84.2 129.1h1.2M84.2 138.8h1.2M84.2 137.6h1.2M84.2 136.3h1.2M84.2 135.1h1.2M84.2 133.9h1.2M84.2 130.3h1.2M84.2 131.5h1.2M84.2 132.7h1.2M105.5 120.5h1.2"/>
<path d="M105.5 121.8h1.2M105.5 123h1.2M105.5 124.2h1.2M105.5 125.4h1.2M105.5 126.6h1.2M105.5 127.8h1.2M105.5 129.1h1.2M150.5 140h1.2M150.5 138.8h1.2M150.5 137.6h1.2M150.5 136.3h1.2M150.5 135.1h1.2"/>
<path d="M150.5 133.9h1.2M157.8 127.8h1.2M157.8 129.1h1.2M157.8 130.3h1.2M157.8 131.5h1.2M166 121.2h1.8M221.9 127.2h1.8M222.8 126v1.2M229.1 129.1h1.9M230.1 127.8v1.3M234.3 138.2h1.2M234.3 137.2v1.9"/>
<path d="M46.9 154h1.8M47.8 152.7v1.3M55.4 154h1.8M56.3 152.7v1.3M61.7 146.1h1.9M61.7 144.8h1.9M63.9 154h1.8M64.8 152.7v1.3M104 149.7h1.8M104.9 148.5v1.2M150.5 142.4h1.2M150.5 141.2h1.2"/>
<path d="M158.4 146.1h1.2M158.4 144.8h1.2M158.4 147.3h1.2M158.4 143.6h1.2M178.1 149.7h1.8M179 148.5v1.2M180.5 149.7h1.9M181.5 148.5v1.2M205.5 149.7h1.8M206.4 148.5v1.2M210.3 149.7h1.8M211.2 148.5v1.2"/>
<path d="M226.4 146.7h1.2M226.4 145.8v1.8M236.7 142.4h1.7M240 142.4h1.6M251.3 143v1.7M251.3 146.2v1.7M252.9 151.5h1.8M253.8 150.3v1.2M254.4 144.3h2.4M254.4 143h2.4M254.4 141.8h2.4"/>
<circle cx="216.7" cy="47" r=".29"/>
<circle cx="178.4" cy="63.4" r=".23"/>
</g>
<g fill="none" stroke="#800000" stroke-width=".19">
<path d="M203.6 57h1.9v.3h-1.9zM203.9 56.1v.6M205.1 56.1v.6M45.3 87.1h3.7v13.4h-3.7zM69 97.7h.3v1.9h-.3zM69.6 99.3h.6M69.6 98.1h.6M181.5 82.9h7.2v7.2h-7.2zM182.1 86.5l3.6-2.4v4.8zM61.1 146.1h.6M61.1 144.8h.6M62.1 144.5h.3v1.9h-.3z"/>
<path d="M256.2 140.6h3v4.9h-3z"/>
</g>
<g fill="none" stroke="#800000" stroke-width=".29">
<path d="M157.8 44h.6M157.8 45.2h.6M157.8 51.3h.6M157.8 52.5h.6M157.8 53.7h.6M157.8 54.9h.6M157.8 71.9h.6M157.8 73.1h.6M157.8 74.4h.6M157.8 75.6h.6M45.9 93.2h.6M45.9 92h.6"/>
<path d="M45.9 90.8h.6M45.9 89.6h.6M45.9 88.3h.6M45.9 94.4h.6M45.9 95.6h.6M45.9 96.8h.6M45.9 98.1h.6M45.9 99.3h.6M47.8 93.2h.6M47.8 92h.6M47.8 90.8h.6M47.8 89.6h.6"/>
<path d="M47.8 88.3h.6M47.8 94.4h.6M47.8 95.6h.6M47.8 96.8h.6M47.8 98.1h.6M47.8 99.3h.6M95.8 98.7h.6M96.4 84.1h.6M158.4 97.5h.6M158.4 99.9h.6M83 116.9h.6M83 119.3h.6"/>
<path d="M83 105.3h.6M83 107.8h.6M83 110.2h.6M83 112.6h.6M96.4 106h.6M96.4 107.2h.6M104.9 103.5h.6M104.9 104.7h.6M104.9 108.4h.6M104.9 109.6h.6M104.9 110.8h.6M104.9 112h.6"/>
<path d="M104.9 113.2h.6M104.9 114.5h.6M104.9 115.7h.6M104.9 116.9h.6M104.9 118.1h.6M104.9 119.3h.6M158.4 103.5h.6M158.4 104.7h.6M158.4 106h.6M158.4 107.2h.6M158.4 108.4h.6M158.4 109.6h.6"/>
<path d="M158.4 110.8h.6M158.4 113.2h.6M158.4 101.1h.6M158.4 102.3h.6M83 121.8h.6M83 124.2h.6M85.4 127.8h.6M85.4 129.1h.6M85.4 138.8h.6M85.4 137.6h.6M85.4 136.3h.6M85.4 135.1h.6"/>
<path d="M85.4 133.9h.6M85.4 130.3h.6M85.4 131.5h.6M85.4 132.7h.6M104.9 120.5h.6M104.9 121.8h.6M104.9 123h.6M104.9 124.2h.6M104.9 125.4h.6M104.9 126.6h.6M104.9 127.8h.6M104.9 129.1h.6"/>
<path d="M151.7 140h.6M151.7 138.8h.6M151.7 137.6h.6M151.7 136.3h.6M151.7 135.1h.6M151.7 133.9h.6M159 127.8h.6M159 129.1h.6M159 130.3h.6M159 131.5h.6M151.7 142.4h.6M151.7 141.2h.6"/>
<path d="M159.6 147.3h.6M159.6 146.1h.6M159.6 144.8h.6M159.6 143.6h.6M256.8 141.8h.6M256.8 143h.6M256.8 144.3h.6"/>
</g>
<g fill="#800000" stroke="#800000" stroke-width=".13">
<path d="M239.3 141.8a.59 .59 0 0 1 .6 .6 .59 .59 0 0 1-.6 .6z" fill-rule="evenodd"/>
<path d="M238.6 142l.4-.2v1.2a.6 .6 0 0 1-.6-.4 .6 .6 0 0 1 .2-.6z" fill-rule="evenodd"/>
<path d="M250.9 144.8a.61 .61 0 0 1 .6-.1 .61 .61 0 0 1 .4 .6h-1.2z" fill-rule="evenodd"/>
<path d="M250.7 145.6h1.2a.6 .6 0 0 1-.6 .6 .6 .6 0 0 1-.6-.6z" fill-rule="evenodd"/>
</g>
<path d="M37.6 55.1h3.3v.9h-3.3z" fill="#800000"/>
<g fill="none" stroke="#800000" stroke-width=".13">
<path d="M33.8 26.9h1.2M36.8 26.9h1.3M37.4 30.6h2.5M37.4 33h2.5M37.7 31.5h.7M38.1 31.5l.3 .6h-.7zM38.1 26.5h2.4v.9h-2.4zM38.1 30.6v.9M38.1 32.1v.9M39 30.6v1.2h.9M39.6 31.5l-.6 .3 .6 .3M39.9 30.1v3.5"/>
<path d="M40.4 30.6v2.4M40.4 30.6h1.9M40.5 26.9h1.2M52 30.6h1.2M53.2 30.2h2.5v.8h-2.5zM55.7 30.6h1.2M60.5 31.8v1.2l1 .5M60.5 35.5v1.2M60.9 35l.2 .5h-.6zM61.5 33h.3v2.4h-.3zM61.6 34.9l-.6 .3M61.7 34.2h1.3"/>
<path d="M63.8 36.1h.8v2.4h-.8zM64.2 34.9v1.2M64.2 38.5v1.2M65.4 34.2h1.2M65.4 30.6h1.2M66.6 30.2h2.4v.8h-2.4zM66.6 33.8h2.4v.9h-2.4zM69 34.2h1.2M69 30.6h1.2M153.7 38.5h.8v2.4h-.8zM154.1 35.5v1.2M154.1 37.3v1.2"/>
<path d="M155.5 38.5h.9v2.4h-.9zM155.9 35.5v1.2M155.9 37.3v1.2M173.5 35.5h2.5M173.5 37.9h2.5M185.7 36.7h2.4M185.7 39.1h2.4M205.6 38.2h2.6v.5h-2.6zM208.2 38.5h1.2M209.4 39.7h-2.1v1.1M220.3 33l.7 1-.7-.4-.6 .4zM220.3 33.6v1.3"/>
<path d="M221 38.5h1.2M227 38.5h1.2M229.6 39.7h.9v2.4h-.9zM230.1 38.5v1.2M238.6 38.5h2.4M238.6 37.3h2.4M238.6 36.1h2.4M243.4 38.5h2.5M243.4 37.3h2.5M243.4 36.1h2.5M246.5 34l.6-1 .6 1M247.1 33v1.2"/>
<path d="M248.9 38.5h1.2M255 38.5h1.2M258.6 39.1v1.2M267.7 36.1v1.2M267.7 39.1v3.7M28.9 59.2v1.2M33.8 59.2v1.2M37.6 55h3.3v1h-3.3zM45.3 59.2h1.2M45.3 51.9h1.2M46.5 48.2h1.3M46.5 58.7h2.5v.9h-2.5z"/>
<path d="M46.5 51.5h2.5v.8h-2.5zM46.5 59.9h2.5v.9h-2.5zM49 59.2h1.2M49 51.9h1.2M53.2 49.4h1.3M53.2 48.2h1.3M54.5 49h2.4v.9h-2.4zM54.5 47.8h2.4v.8h-2.4zM56.9 49.4h1.2M56.9 48.2h1.2M63 49.4h2.4M63 48.2h2.4"/>
<path d="M63 45.2h1.6M63 59.2h2.4M63 51.9h2.4M63 56.7h2.4M63 53.1h2.4M63 55.5h2.4M63 54.3h2.4M63 58h2.4M65.4 47h9.7v19.5h-9.7zM66.2 45.2h1.6M71.2 47.6l-1.2 .6h-1.3M71.2 48.2h.9v1.2h-3.4"/>
<path d="M81.8 57.3h1.2M92.9 43.4h.9v2.4h-.9zM93.3 40.9v2.5M93.3 45.8v1.2M97 40.9v1.2M100.6 40.9v1.2M104.3 40.9v1.2M106.7 58.5h2.4M106.7 56.1h2.4M106.7 57.3h2.4M106.7 46.4h2.4M106.7 48.8h2.4"/>
<path d="M106.7 44h2.4M106.7 51.3h2.4M106.7 52.5h2.4M106.7 53.7h2.4M109.1 42.8h38.9v105.7h-38.9zM148 59.8h2.5M148 58.5h2.5M148 56.1h2.5M148 57.3h2.5M148 45.2h2.5M148 47.6h2.5M148 46.4h2.5"/>
<path d="M148 48.8h2.5M148 50h2.5M148 44h2.5M148 51.3h2.5M148 52.5h2.5M148 53.7h2.5M148 54.9h2.5M154.1 40.9v1.2M155.9 40.9v1.2M166.3 56.1h1.2M166.3 57.3h1.2M167.5 55.7h2.4v.9h-2.4z"/>
<path d="M167.5 56.9h2.4v.9h-2.4zM169.9 56.1h1.2M169.9 57.3h1.2M172.3 56.1h1.2M172.3 57.3h1.2M173.5 40.3h2.5M173.5 42.8h2.5M173.5 45.2h2.5M173.5 46.4h2.5M173.5 48.8h2.5M173.5 50h2.5M185.3 58.5h.8v2.5h-.8z"/>
<path d="M185.7 56.1v2.4M185.7 45.2h2.4M185.7 46.4h2.4M185.7 48.8h2.4M185.7 50h2.4M186.3 53.7h1.2M188.7 53.7h2.5M191.2 45.2h2.4M191.2 47.6h2.4M191.2 46.4h2.4M191.2 48.8h2.4M191.2 50h2.4"/>
<path d="M193.6 53.7h2.4M194 46a.41 .41 0 0 0-.4 .4 .41 .41 0 0 0 .4 .4M194 44.8a.41 .41 0 0 0-.4 .4 .41 .41 0 0 0 .4 .4M194 47.2a.41 .41 0 0 0-.4 .4 .41 .41 0 0 0 .4 .4M194 48.4a.41 .41 0 0 0-.4 .4 .41 .41 0 0 0 .4 .4M194 49.6a.42 .42 0 0 0-.4 .4 .42 .42 0 0 0 .4 .5M194.8 44h3.7M194.8 51.3h3.7M195.5 46a.41 .41 0 0 1 .5 .4 .41 .41 0 0 1-.5 .4M195.5 48.4a.41 .41 0 0 1 .5 .4 .41 .41 0 0 1-.5 .4M195.5 47.2a.41 .41 0 0 1 .5 .4 .41 .41 0 0 1-.5 .4M195.5 49.6a.42 .42 0 0 1 .5 .4 .42 .42 0 0 1-.5 .5"/>
<path d="M196 47.6h2.5M196 46.4h2.5M196 48.8h2.5M196 50h2.5M200.3 59.8v1.2M203.9 59.8v1.2M205.6 40.9l.6-.8 .8 .8h2.4M207.2 40.4h.3l-.2 .4zM207.8 59.8h.8v2.4h-.8zM208.2 56.1v1.2M208.2 58.5v1.3M223.6 59.8h.8v2.4h-.8z"/>
<path d="M224 56.1v1.2M224 58.5v1.3M224.6 44.6h1.2M224.6 47h1.2M224.6 40.9v1.2M225.8 44.2h2.4v.8h-2.4zM225.8 46.6h2.4v.8h-2.4zM228.2 44.6h1.3M228.2 47h1.3M230.1 42.1v1.3M246.5 59.8v1.2M252.1 45.2h.9v2.4h-.9z"/>
<path d="M252.5 40.9v1.2M252.5 44v1.2M252.5 47.6v1.2M258.2 40.3h.9v2.5h-.9zM258.6 42.8v1.2M266.3 41.5l.3 .2-.4 .2zM266.8 40.7l-.7 .7 .4-.2-.2-.3-.2 .5M266.8 41.2l-.6 .7M267.1 40.3h1.2l-.6 1.3zM267.1 41.6h1.2M267.3 44.3h.9v2.4h-.9zM267.7 43.1v1.2"/>
<path d="M267.7 46.7v1.2M28.5 60.4h.9v2.4h-.9zM28.9 62.8v1.2M32.4 67.6l.2 .3-.4 .1zM32.8 66.8l-.7 .7 .5-.2-.3-.2-.2 .4M32.9 67.4l-.7 .6M33.2 66.5h1.2l-.6 1.2zM33.2 67.7h1.2M33.4 60.4h.8v2.4h-.8zM33.8 62.8v1.2M33.8 65.2v3.7M45.3 60.4h1.2"/>
<path d="M45.3 61.6h1.2M46.5 64h1.3M46.5 61.2h2.5v.8h-2.5zM49 60.4h1.2M49 61.6h1.2M53.2 64h1.3M53.2 65.2h1.3M54.5 63.6h2.4v.9h-2.4zM54.5 64.8h2.4v.9h-2.4zM56.9 64h1.2M56.9 65.2h1.2M63 60.4h2.4"/>
<path d="M63 64h2.4M63 65.2h2.4M63 61.6h2.4M71.2 63.4l-1.2 .6h-1.3M71.2 64h.9v1.2h-3.4M103.1 72.5h1.7M104.6 79.1h1.7M104.6 78.1h1.7M104.6 73h1.7M104.6 72.1h1.7M104.8 78.4h1.4v.4h-1.4zM104.8 72.3h1.4v.4h-1.4z"/>
<path d="M105.5 71.3v.8M105.5 73v.7M105.5 77.4v.7M105.5 79.1v.7M106.7 62.2h2.4M106.7 61h2.4M106.7 63.4h2.4M106.7 67.1h2.4M106.7 64.6h2.4M106.7 76.8h2.4M106.7 65.8h2.4M106.7 70.7h2.4"/>
<path d="M106.7 74.4h2.4M148 62.2h2.5M148 61h2.5M148 63.4h2.5M148 67.1h2.5M148 64.6h2.5M148 76.8h2.5M148 78h2.5M148 65.8h2.5M148 68.3h2.5M148 69.5h2.5M148 70.7h2.5"/>
<path d="M148 71.9h2.5M148 73.1h2.5M148 74.4h2.5M148 75.6h2.5M148 79.2h2.5M165.6 67.1h1.3M165.6 76.8h1.3M165.6 78h1.3M166.9 76.4h2.4v.8h-2.4zM166.9 77.6h2.4v.8h-2.4zM168.1 67.1h1.2M169.3 76.8h1.2"/>
<path d="M169.3 78h1.2M172.9 76.8h1.3M172.9 78h1.3M172.9 69.5v1.2M176.6 67.1h1.2M182.1 60.4v1.8M183.3 60.4v1.8M185.7 61v1.2M191.8 64.6v2M191.8 68.8v1.9M192.4 78.6v1.2M192.6 66.8v1.7"/>
<path d="M192.7 67.7h1M193.7 67.4v.5M199.9 61h.8v2.4h-.8zM200.3 63.4v1.2M200.9 78.6v2.4M201.5 67.1h1.2M202.6 65.8h.3v2.5h-.3zM202.9 67.8l.6 .2M203.5 61h.9v2.4h-.9zM203.6 67.8l.3 .5h-.6zM203.9 63.4v2.4l-.9 .5M203.9 68.3v1.2"/>
<path d="M208.2 62.2v1.2M216.7 78.6v2.4M223.4 66.5h1.2l-.6 1.2zM223.4 67.7h1.2M224 62.2v1.2M224 65.2v3.7M224.9 67.4l.7 .6M225 66.8l.6 .7-.4-.2 .2-.2 .2 .4M225.4 67.6l.2 .4-.5-.1zM237.4 71.9h3.6M238.2 70.3l.4 .2-.2 .3zM238.2 70.3l.7 .7"/>
<path d="M238.6 71.9l1.2-.6v1.2zM238.6 71.3v1.2M238.8 70.3l.4 .2-.3 .2-.1-.4 .6 .7M239.2 78.6h1.8M239.2 79.8h1.8M239.2 77.4h1.8M241.8 64.6h.9v2.5h-.9zM242.2 62.2v2.4M242.2 67.1v1.2M246 72.5h.9v2.5h-.9zM246 64.6h.9v2.5h-.9zM246.5 63.4v1.2"/>
<path d="M246.5 67.1v1.2M246.5 71.3v1.2M246.5 75v1.2M247.7 68.9h1.2M248.8 67.7h.3v2.4h-.3zM249.1 69.6l1 .5v1.2M249.7 67.6l.2 .5-.8 .1zM249.7 76.2h.8v2.4h-.8zM250.1 62.2v1.2M250.1 66.5v1.2l-.3 .2M250.1 75v1.2M250.1 78.6v1.2"/>
<path d="M251.3 72.5h1.2l-.6 1.2zM251.3 73.7h1.2M251.5 76.2h.9v2.4h-.9zM251.9 71.3v4.9M251.9 78.6v1.2M252.9 73.4l.6 .7M252.9 72.9l.7 .7-.4-.2 .2-.3 .2 .5M253.3 73.7l.2 .4-.4-.2zM259.8 79.8h2.5v6.1h-2.5zM54.6 85.3h.9v2.4h-.9zM55.1 84.1v1.2M55.1 87.7v1.2"/>
<path d="M58.9 85.3h.8v2.4h-.8zM59.3 84.1v1.2M59.3 87.7v1.2M62.5 85.3h.9v2.4h-.9zM63 84.1v1.2M63 87.7v1.2M66.2 85.3h.8v2.4h-.8zM66.6 82.3v1.2M66.6 84.1v1.2M66.6 87.7v1.2M80.8 90.1h.8v2.5h-.8zM80.8 98.1h.8v2.4h-.8z"/>
<path d="M81.2 85.3v1.2M81.2 88.9v1.2M81.2 92.6v1.2M81.2 96.8v1.3M98.8 85.9l.6 .6-.6 .6-.6-.6zM99.4 86.5h1.2M106.7 90.1h2.4M106.7 92.6h2.4M106.7 93.8h2.4M106.7 80.4h2.4M106.7 85.3h1.5M106.7 87.7h2.4"/>
<path d="M106.7 86.5h2.4M106.7 98.7h2.4M106.7 96.2h2.4M106.7 88.9h2.4M106.7 91.4h2.4M148 90.1h2.5M148 92.6h2.5M148 93.8h2.5M148 80.4h2.5M148 85.3h2.5M148 87.7h2.5M148 86.5h2.5"/>
<path d="M148 98.7h2.5M148 96.2h2.5M148 81.6h2.5M148 88.9h2.5M148 91.4h2.5M148 95h2.5M148 97.5h2.5M148 99.9h2.5M148 82.9h2.5M173.1 96.8h.9v2.5h-.9zM173.5 95.6v1.2M173.5 99.3v1.2"/>
<path d="M175.4 93.8h1.2M176.6 93.3h2.4v1h-2.4zM179 93.8h1.2M181.5 93.8h1.2M181.8 80.4h1.2M183 80h2.4v.9h-2.4zM185.4 80.4h1.2M185.7 98.1h1.2M186.9 97.6h2.5v1h-2.5zM189.4 98.1h1.2M200.5 81h.8v2.5h-.8zM200.9 83.5v1.2"/>
<path d="M201.5 84.7h1.2M202.7 84.3h2.4v.8h-2.4zM205.1 84.7h1.3M216.3 81h.8v2.5h-.8zM216.7 83.5v1.2M217.3 84.7h1.2M218.5 84.3h2.5v.8h-2.5zM221 84.7h1.2M227.6 99.3v1.2M230.1 99.3v1.2M232.5 99.3v1.2M234.9 99.3v1.2"/>
<path d="M237.4 99.3v1.2M243.4 83.5h1.2M243.4 85.9h1.2M244.6 83h2.5v.9h-2.5zM244.6 85.5h2.5v.8h-2.5zM247.1 83.5h1.2M247.1 85.9h1.2M251.3 93.2h1.2M252.7 99.6h.9v2.4h-.9zM253.2 98.4v1.2M258.6 81h1.2M258.6 83.5h1.2"/>
<path d="M258.6 84.7h1.2M258.6 82.3h1.2M261 98.1h1.3M261 93.2h1.3M261 94.4h1.3M261 95.6h1.3M261 96.8h1.3M261 99.3h1.3M50.2 119.3h2.4M50.2 116.9h2.4M50.2 118.1h2.4M52.6 115.7h7.3v29.1h-7.3z"/>
<path d="M54.6 101.7h.9v2.4h-.9zM55.1 100.5v1.2M55.1 104.1v1.2M58.9 101.7h.8v2.4h-.8zM59.3 100.5v1.2M59.3 104.1v1.2M59.9 119.3h2.5M59.9 116.9h2.5M59.9 118.1h2.5M62.5 101.7h.9v2.4h-.9zM63 100.5v1.2M63 104.1v1.2"/>
<path d="M66.2 101.7h.8v2.4h-.8zM66.6 100.5v1.2M66.6 104.1v1.2M78.8 105.3l.9-.6-.3 .6 .3 .7zM78.8 107.8h1.2M79.4 116.9l.9-.6-.3 .6 .3 .6zM79.4 110.2h1.2M79.4 119.3h1.2M79.4 105.3h1.2M79.7 107.2l-.9 .6 .9 .6M80 116.9h1.2M80.3 118.7l-.9 .6 .9 .6"/>
<path d="M81.2 100.5v1.2M106.7 103.5h2.4M106.7 119.3h2.4M106.7 112h2.4M106.7 114.5h2.4M106.7 110.8h2.4M106.7 115.7h2.4M106.7 116.9h2.4M106.7 118.1h2.4M106.7 104.7h2.4M106.7 106h2.4M106.7 107.2h2.4"/>
<path d="M106.7 108.4h2.4M106.7 109.6h2.4M106.7 113.2h2.4M148 103.5h2.5M148 119.3h2.5M148 112h2.5M148 110.8h2.5M148 115.7h2.5M148 116.9h2.5M148 118.1h2.5M148 101.1h2.5M148 102.3h2.5"/>
<path d="M148 104.7h2.5M148 106h2.5M148 107.2h2.5M148 108.4h2.5M148 109.6h2.5M148 113.2h2.5M166.4 105.3h1v2.5h-1zM166.4 114.5h1v2.4h-1zM166.9 104.1v1.2M166.9 107.8v1.2M166.9 113.2v1.3M166.9 116.9v1.2"/>
<path d="M171.8 111.4h1v2.5h-1zM172.3 107.8v1.2M172.3 110.2v1.2M172.3 113.9v1.2M182.7 117.5h2.4M182.7 116.3h2.4M182.7 118.7h2.4M182.7 119.9h2.4M184.5 103.5h1.2M185.1 111.4h24.3v25.5h-24.3zM185.7 103.5a.59 .59 0 0 1 .6-.6 .59 .59 0 0 1 .6 .6 .6 .6 0 0 1 .6-.6 .6 .6 0 0 1 .6 .6M188.1 103.5a.6 .6 0 0 1 .6-.6 .6 .6 0 0 1 .6 .6"/>
<path d="M189.4 103.5a.59 .59 0 0 1 .5-.6 .59 .59 0 0 1 .6 .6M190 109v2.4M190.6 103.5h1.2M191.2 109v2.4M192.4 109v2.4M193.6 109v2.4M194.8 109v2.4M196 109v2.4M197.2 109v2.4M198.5 109v2.4M199.7 109v2.4M200.9 109v2.4"/>
<path d="M202.1 109v2.4M203.3 109v2.4M205.5 107.8h1.2M206.7 107.3h2.4v1h-2.4zM209.1 107.8h1.2M209.4 117.5h2.4M209.4 116.3h2.4M209.4 118.7h2.4M209.4 119.9h2.4M213.8 109.6h1v2.4h-1zM214.3 108.4v1.2M214.3 112v1.2"/>
<path d="M216.8 115.1h1v2.4h-1zM217.3 109v1.2M217.3 113.9v1.2M217.3 117.5v1.2M220.3 109v1.2M227.1 100.5h1v2.4h-1zM227.6 102.9v1.2M229.6 100.5h.9v2.4h-.9zM230.1 102.9v1.2M232 100.5h1v2.4h-1zM232.5 102.9v1.2M234.4 100.5h1v2.4h-1z"/>
<path d="M234.9 102.9v1.2M236.9 100.5h.9v2.4h-.9zM237.4 102.9v1.2M238 111.4h2.4M238 113.9h2.4M238 109h2.4M238 112.6h2.4M238 115.1h2.4M238 117.5h2.4M238 116.3h2.4M238 118.7h2.4M238 107.8h2.4"/>
<path d="M238 110.2h2.4M240.4 106.6h20.6v13.3h-20.6zM240.4 110.8h3.6M240.4 115.7h3.6M244 111.4h3.4v.3M244 113.9h3.4v.3M244 109h.6M244 116.3h1.6M244 118.7h1.6M244 107.8h1.6M244 110.2h1.6M244 106.6v13.3"/>
<path d="M244.6 108.9h.1v.2h-.1zM245.2 107.4l.1 .1zM245.2 115.9l.1 .1zM245.6 109h-1v8.5h1M246.2 107.5v3M246.2 116v3M246.8 109h.9v-1.8h3.6v1.8h.9M246.8 116.3h2.7v.6M246.8 107.8h2.4v.6M247 107.4l.1 .1zM247 115.9l.1 .1zM247.1 111.7h.6l-.3 .6z"/>
<path d="M247.1 114.2h.6l-.3 .6zM247.1 112.3h.6M247.1 114.8h.6M247.4 112.3v.3h-3.4M247.4 114.8v.3h-3.4M248 111.7h.1M248 112h.1M248 114.1h.1M248 114.5h.1M248.1 111.8v-.1l-.2 .2M248.1 112.2v-.2l-.2 .3M248.1 114.2v-.1l-.2 .2"/>
<path d="M248.1 114.6v-.1l-.2 .2M248.8 108l.1 .1zM248.8 109.9h.1zM248.9 109h1.5M249.2 117.5h1.5M249.2 109.6v.6h-2.4M249.5 118.1v.6h-2.7M250.1 109.6v1.8h7.3M250.4 118.1v.6h1.8v-1.2h4v1.2h1.2M250.7 116.5v.1zM250.8 118.4h.1M252.2 108.8h1.3v.4h-1.3z"/>
<path d="M252.2 116h1.3v.5h-1.3zM252.2 116.3h-.6v-.6h-3.3v1.8h-1.5M253.2 119.3h1.8M253.2 102v1.2M253.5 109h1.2M253.5 116.3h1.2M253.5 119.5l-.3 .3M253.7 119.5l-.2 .3M253.8 118.7h.6M253.8 118.4h.6M253.9 119.5l-.2 .3M254 108.9h.1v.2h-.1z"/>
<path d="M254 116.2h.1v.2h-.1zM254.1 109v9.4M254.1 118.7v.6M254.2 119.5l-.3 .3M254.4 119.5l-.2 .3M254.7 108.8h1.2v.4h-1.2zM254.7 116h1.2v.5h-1.2zM254.7 119.5l-.3 .3M254.9 119.5l-.2 .3M255.9 109h1.5M255.9 116.3h1.5M256.7 116.2h.2v.2h-.2z"/>
<path d="M256.7 108.9h.2v.2h-.2zM256.8 109v1.2h.6M256.8 116.3v1.2h.6M257.4 107.8h-7.3v.6M257.4 115.1h-7v1.8M257.4 106.6v13.3M261 100.5h1.3M261 101.7h1.3M261 104.1h1.3M261 102.9h1.3M50.2 129.1h2.4M50.2 135.1h2.4"/>
<path d="M50.2 120.5h2.4M50.2 121.8h2.4M50.2 123h2.4M50.2 124.2h2.4M50.2 125.4h2.4M50.2 126.6h2.4M50.2 127.8h2.4M50.2 130.3h2.4M50.2 131.5h2.4M50.2 132.7h2.4M50.2 133.9h2.4M50.2 136.3h2.4"/>
<path d="M50.2 137.6h2.4M50.2 138.8h2.4M59.9 129.1h2.5M59.9 135.1h2.5M59.9 120.5h2.5M59.9 121.8h2.5M59.9 123h2.5M59.9 124.2h2.5M59.9 125.4h2.5M59.9 126.6h2.5M59.9 127.8h2.5M59.9 130.3h2.5"/>
<path d="M59.9 131.5h2.5M59.9 132.7h2.5M59.9 133.9h2.5M59.9 136.3h2.5M59.9 137.6h2.5M59.9 138.8h2.5M66 124.2h1.2M80.6 121.8h1.2M106.7 129.1h2.4M106.7 135.1h2.4M106.7 120.5h2.4M106.7 121.8h2.4"/>
<path d="M106.7 123h2.4M106.7 124.2h2.4M106.7 125.4h2.4M106.7 126.6h2.4M106.7 127.8h2.4M106.7 136.3h2.4M106.7 137.6h2.4M106.7 138.8h2.4M106.7 140h2.4M148 129.1h2.5M148 135.1h2.5M148 120.5h2.5"/>
<path d="M148 121.8h2.5M148 123h2.5M148 124.2h2.5M148 125.4h2.5M148 126.6h2.5M148 127.8h2.5M148 130.3h2.5M148 131.5h2.5M148 133.9h2.5M148 136.3h2.5M148 137.6h2.5M148 138.8h2.5"/>
<path d="M148 140h2.5M177.2 123.6h1.2M182.7 126h2.4M182.7 124.8h2.4M182.7 129.7h2.4M182.7 128.4h2.4M182.7 127.2h2.4M182.7 123.6h2.4M182.7 121.2h2.4M182.7 122.4h2.4M190 136.9v2.5M191.2 136.9v2.5"/>
<path d="M192.4 136.9v2.5M193.6 136.9v2.5M194.8 136.9v2.5M196 136.9v2.5M197.2 136.9v2.5M198.5 136.9v2.5M199.7 136.9v2.5M200.9 136.9v2.5M202.1 136.9v2.5M203.3 136.9v2.5M209.4 126h2.4M209.4 124.8h2.4"/>
<path d="M209.4 129.7h2.4M209.4 128.4h2.4M209.4 127.2h2.4M209.4 123.6h2.4M209.4 121.2h2.4M209.4 122.4h2.4M211.2 138.2v1.2M215.5 129.1h1.2M215.5 126h1.2M215.5 132.1h1.2M215.5 135.1h1.2M216.7 128.6h2.4v.9h-2.4z"/>
<path d="M216.7 125.5h2.4v1h-2.4zM216.7 131.6h2.4v1h-2.4zM216.7 134.6h2.4v1h-2.4zM219.1 129.1h1.2M219.1 126h1.2M219.1 132.1h1.2M219.1 135.1h1.2M231.9 139.1l.6-.9 .6 .9M232.5 138.2v1.2M236.7 138.2h1.3M238 137.7h2.4v.9h-2.4zM240.4 138.2h1.2"/>
<path d="M250.9 139.4h.9v2.4h-.9zM251.3 138.2v1.2M53.8 144.8v2.5M55.1 144.8v2.5M56.3 144.8v2.5M57.5 144.8v2.5M58.7 144.8v2.5M64.4 148.5h.8v2.4h-.8zM64.8 147.3v1.2M64.8 150.9v1.2M106.7 141.2h2.4M106.7 142.4h2.4"/>
<path d="M106.7 143.6h2.4M106.7 144.8h2.4M106.7 147.3h2.4M148 141.2h2.5M148 142.4h2.5M148 143.6h2.5M148 144.8h2.5M148 146.1h2.5M148 147.3h2.5M182.7 141.2h1.2M183.9 141.2a.6 .6 0 0 1 .6-.6 .6 .6 0 0 1 .6 .6M185.1 141.2a.59 .59 0 0 1 .6-.6 .59 .59 0 0 1 .6 .6 .61 .61 0 0 1 .6-.6 .61 .61 0 0 1 .6 .6 .6 .6 0 0 1 .6-.6 .6 .6 0 0 1 .6 .6"/>
<path d="M188.7 141.2h1.3M199.2 144.3h1v2.4h-1zM199.7 143v1.3M199.7 146.7v2.4M225.8 149.1h1.2M227 148.7h2.5v.8h-2.5zM229.5 149.1h1.2M233.1 149.1h1.2M233.1 146.7h1.2M233.1 147.9h1.2M233.1 145.5h1.2M242.8 149.1h1.2"/>
<path d="M242.8 146.7h1.2M242.8 147.9h1.2M242.8 145.5h1.2M251.3 141.8v1.2"/>
<circle cx="33.2" cy="26.9" r=".6"/>
<circle cx="154.1" cy="34.8" r=".59"/>
<circle cx="155.9" cy="34.8" r=".6"/>
<circle cx="267.7" cy="35.5" r=".6"/>
<circle cx="45.9" cy="48.2" r=".59"/>
<circle cx="81.2" cy="57.3" r=".61"/>
<circle cx="93.3" cy="40.3" r=".61"/>
<circle cx="97" cy="40.3" r=".6"/>
<circle cx="100.6" cy="40.3" r=".6"/>
<circle cx="104.3" cy="40.3" r=".6"/>
<circle cx="174.1" cy="57.3" r=".61"/>
<circle cx="174.1" cy="56.1" r=".6"/>
<circle cx="185.7" cy="55.5" r=".6"/>
<circle cx="185.7" cy="53.7" r=".59"/>
<circle cx="208.2" cy="55.5" r=".6"/>
<circle cx="224" cy="55.5" r=".61"/>
<circle cx="246.5" cy="59.1" r=".6"/>
<circle cx="45.9" cy="64" r=".6"/>
<circle cx="165" cy="67.1" r=".59"/>
<circle cx="174.8" cy="78" r=".61"/>
<circle cx="174.8" cy="76.8" r=".6"/>
<circle cx="191.8" cy="68.5" r=".23"/>
<circle cx="191.8" cy="66.8" r=".23"/>
<circle cx="192.4" cy="78" r=".6"/>
<circle cx="200.9" cy="78" r=".6"/>
<circle cx="216.7" cy="78" r=".6"/>
<circle cx="242.2" cy="61.6" r=".6"/>
<circle cx="250.1" cy="61.6" r=".6"/>
<circle cx="66.6" cy="81.6" r=".6"/>
<circle cx="81.2" cy="84.7" r=".61"/>
<circle cx="98.8" cy="86.5" r=".29"/>
<circle cx="108.6" cy="85.3" r=".46"/>
<circle cx="183.3" cy="93.8" r=".59"/>
<circle cx="250.7" cy="93.2" r=".6"/>
<circle cx="78.7" cy="110.2" r=".6"/>
<circle cx="172.3" cy="107.2" r=".6"/>
<circle cx="217.3" cy="108.4" r=".59"/>
<circle cx="220.3" cy="108.4" r=".6"/>
<circle cx="67.8" cy="124.2" r=".6"/>
<circle cx="80" cy="121.7" r=".59"/>
<circle cx="176.6" cy="123.6" r=".6"/>
<circle cx="211.2" cy="137.5" r=".59"/>
<circle cx="199.7" cy="149.7" r=".61"/>
</g>
<path d="M245.6 107.8v2.4M245.6 116.3v2.4M246.8 107.8v2.4M246.8 116.3v2.4M249.2 108.4h.9M249.2 109.6h.9M249.5 116.9h.9M249.5 118.1h.9" fill="none" stroke="#800000" stroke-width=".48"/>
<path d="M205.7 38.5h2.5" fill="none" stroke="#800000" stroke-width=".44"/>
<g fill="none" stroke="#800000" stroke-width=".19">
<path d="M176 34.2h9.7v17.1h-9.7zM222.2 37.3h4.8v3.6h-4.8zM240.4 34.9h3.6v4.8h-3.6zM250.1 37.3h4.9v3.6h-4.9zM182.1 59.8v.6M183.3 59.8v.6M192.9 44.3v6.6a.58 .58 0 0 0 .7 .6M193.6 43.7h-.1a.59 .59 0 0 0-.6 .6M193.6 43.7l2.7 .6 .4 .3v.3M196.7 50.3v.3l-.4 .3-2.7 .6M196.8 44.9v5.5M169.3 65.8h7.3v3.7h-7.3z"/>
<path d="M181.8 60.7h1.8v.3h-1.8zM238.6 77.4h.6M238.6 78.6h.6M238.6 79.8h.6M239.5 77.1h.3v3h-.3zM234.3 144.3h8.5v6h-8.5z"/>
</g>
<g fill="none" stroke="#800000" stroke-width=".29">
<path d="M241 36.1h.6M241 37.3h.6M241 38.5h.6M242.8 36.1h.6M242.8 37.3h.6M242.8 38.5h.6M194.7 43.9h.2v.1h-.2zM194.7 51.2h.2v.1h-.2zM262.3 93.2h.6M262.3 94.4h.6M262.3 95.6h.6M262.3 96.8h.6"/>
<path d="M262.3 98.1h.6M262.3 99.3h.6M262.3 100.5h.6M262.3 101.7h.6M262.3 102.9h.6M262.3 104.1h.6"/>
</g>
<path d="M61.7 33.1v2.3M202.8 65.9v2.4" fill="none" stroke="#800000" stroke-width=".32"/>
<path d="M249 67.7v2.4" fill="none" stroke="#800000" stroke-width=".34"/>
<g fill="#800000" stroke="#800000" stroke-width=".13">
<path d="M65.5 44.6a.59 .59 0 0 1 .7 .6 .59 .59 0 0 1-.7 .6z" fill-rule="evenodd"/>
<path d="M64.8 44.7l.4-.1v1.2a.6 .6 0 0 1-.6-.4 .6 .6 0 0 1 .2-.7z" fill-rule="evenodd"/>
</g>
<path d="M88.5 92.6v-9.7l-1.2-1.3h-12.2l-1.2 1.3v26.7l-1.2 1.2h-29.8l-1.2 1.2v15.8M169.3 85.3v65l1.2 1.2h29.2M161.4 115.7v35.8l-1.2 1.2h-86.3l-1.2-1.2v-32.2" fill="none" stroke="#000080" stroke-width=".36"/>
<g fill="#008000" stroke="#008000" stroke-width=".13">
<path d="M54.9 99.1h.3l.1 .2-.1 .1-.1 .1-.2-.1z" fill-rule="evenodd"/>
<path d="M105.3 57.2h.4v.1v.2l-.2 .1-.2-.1z" fill-rule="evenodd"/>
<path d="M172.2 116.1h.3v.2v.1l-.2 .1-.1-.1z" fill-rule="evenodd"/>
<path d="M104.7 141h.3l.1 .2-.1 .1-.1 .1-.2-.1z" fill-rule="evenodd"/>
<path d="M197.1 57.2h.3l.1 .1-.1 .2-.2 .1-.1-.1z" fill-rule="evenodd"/>
<path d="M42.1 99.1h.4v.2v.1l-.2 .1-.2-.1z" fill-rule="evenodd"/>
<path d="M71.3 34.1h.3l.1 .1-.1 .2-.1 .1-.2-.1z" fill-rule="evenodd"/>
<path d="M64 34.1h.3l.1 .1-.1 .2-.1 .1-.2-.1z" fill-rule="evenodd"/>
<path d="M189.8 141h.3l.1 .2-.1 .1-.2 .1-.1-.1z" fill-rule="evenodd"/>
<circle cx="232.5" cy="142.4" r=".23"/>
<circle cx="232.5" cy="140.6" r=".23"/>
<circle cx="247.1" cy="36.1" r=".23"/>
<circle cx="247.1" cy="37.3" r=".23"/>
<circle cx="247.1" cy="38.5" r=".23"/>
<circle cx="228.2" cy="38.5" r=".23"/>
<circle cx="230.1" cy="38.5" r=".23"/>
<circle cx="233.1" cy="38.5" r=".23"/>
<circle cx="235.5" cy="38.5" r=".23"/>
<circle cx="220.3" cy="38.5" r=".23"/>
<circle cx="105.5" cy="56.1" r=".23"/>
<circle cx="97" cy="54.9" r=".23"/>
<circle cx="222.8" cy="122.3" r=".23"/>
<circle cx="197.2" cy="103.5" r=".23"/>
<circle cx="202.1" cy="103.5" r=".23"/>
<circle cx="227.6" cy="97.4" r=".23"/>
<circle cx="230.1" cy="97.4" r=".23"/>
<circle cx="237.3" cy="97.4" r=".23"/>
<circle cx="236.1" cy="97.4" r=".23"/>
<circle cx="100.6" cy="50" r=".23"/>
<circle cx="89.7" cy="61" r=".23"/>
<circle cx="89.7" cy="62.2" r=".23"/>
<circle cx="89.7" cy="63.4" r=".23"/>
<circle cx="89.7" cy="64.6" r=".23"/>
<circle cx="89.7" cy="65.8" r=".23"/>
<circle cx="89.7" cy="67.1" r=".23"/>
<circle cx="251.3" cy="138.2" r=".23"/>
<circle cx="251.3" cy="147.9" r=".23"/>
<circle cx="61.7" cy="64" r=".23"/>
<circle cx="250.1" cy="83.5" r=".23"/>
<circle cx="81.2" cy="96.2" r=".23"/>
<circle cx="173.5" cy="93.8" r=".23"/>
<circle cx="104.9" cy="147.3" r=".23"/>
<circle cx="104.9" cy="136.3" r=".23"/>
<circle cx="104.9" cy="137.5" r=".23"/>
<circle cx="104.9" cy="138.8" r=".23"/>
<circle cx="104.9" cy="140" r=".23"/>
<circle cx="104.9" cy="142.4" r=".23"/>
<circle cx="104.9" cy="143.6" r=".23"/>
<circle cx="104.9" cy="144.8" r=".23"/>
<circle cx="77.5" cy="61" r=".23"/>
<circle cx="77.5" cy="62.2" r=".23"/>
<circle cx="77.5" cy="63.4" r=".23"/>
<circle cx="77.5" cy="64.6" r=".23"/>
<circle cx="77.5" cy="65.8" r=".23"/>
<circle cx="77.5" cy="67.1" r=".23"/>
<circle cx="77.5" cy="53.7" r=".23"/>
<circle cx="77.5" cy="52.5" r=".23"/>
<circle cx="77.5" cy="51.2" r=".23"/>
<circle cx="77.5" cy="50" r=".23"/>
<circle cx="94.5" cy="80.4" r=".23"/>
<circle cx="94.5" cy="74.3" r=".23"/>
<circle cx="94.5" cy="76.8" r=".23"/>
<circle cx="94.5" cy="72.5" r=".23"/>
<circle cx="200.3" cy="39.1" r=".23"/>
<circle cx="230.6" cy="146.7" r=".23"/>
<circle cx="42.3" cy="98" r=".23"/>
<circle cx="42.3" cy="96.8" r=".23"/>
<circle cx="42.3" cy="95.6" r=".23"/>
<circle cx="42.3" cy="94.4" r=".23"/>
<circle cx="42.3" cy="93.2" r=".23"/>
<circle cx="42.3" cy="92" r=".23"/>
<circle cx="42.3" cy="90.8" r=".23"/>
<circle cx="47.7" cy="131.5" r=".23"/>
<circle cx="47.7" cy="132.7" r=".23"/>
<circle cx="47.7" cy="133.9" r=".23"/>
<circle cx="47.7" cy="135.1" r=".23"/>
<circle cx="47.7" cy="136.3" r=".23"/>
<circle cx="47.7" cy="137.5" r=".23"/>
<circle cx="47.7" cy="138.8" r=".23"/>
<circle cx="56.3" cy="150.9" r=".23"/>
<circle cx="57.5" cy="150.9" r=".23"/>
<circle cx="55" cy="150.9" r=".23"/>
<circle cx="64.8" cy="125.4" r=".23"/>
<circle cx="64.8" cy="126.6" r=".23"/>
<circle cx="64.8" cy="127.8" r=".23"/>
<circle cx="181.4" cy="129.6" r=".23"/>
<circle cx="181.4" cy="146.7" r=".23"/>
<circle cx="181.4" cy="144.2" r=".23"/>
<circle cx="212.4" cy="116.3" r=".23"/>
<circle cx="214.2" cy="116.3" r=".23"/>
<circle cx="197.2" cy="95.6" r=".23"/>
<circle cx="196" cy="101.1" r=".23"/>
<circle cx="194.8" cy="101.1" r=".23"/>
<circle cx="178.4" cy="101.1" r=".23"/>
<circle cx="178.4" cy="103.5" r=".23"/>
<circle cx="178.4" cy="105.9" r=".23"/>
<circle cx="220.3" cy="47" r=".23"/>
<circle cx="60.5" cy="57.9" r=".23"/>
<circle cx="208.2" cy="64.6" r=".23"/>
<circle cx="220.3" cy="129" r=".23"/>
<circle cx="105.5" cy="76.8" r=".23"/>
<circle cx="97" cy="48.8" r=".23"/>
<circle cx="105.5" cy="80.4" r=".23"/>
<circle cx="105.5" cy="70.7" r=".23"/>
<circle cx="105.5" cy="74.3" r=".23"/>
<circle cx="200.3" cy="67.1" r=".23"/>
<circle cx="200.9" cy="84.7" r=".23"/>
<circle cx="154.1" cy="44" r=".23"/>
<circle cx="61.7" cy="48.2" r=".23"/>
<circle cx="62.9" cy="49.4" r=".23"/>
<circle cx="62.9" cy="65.2" r=".23"/>
<circle cx="250.1" cy="71.3" r=".23"/>
<circle cx="246.5" cy="68.9" r=".23"/>
<circle cx="42.3" cy="30.6" r=".23"/>
<circle cx="60.5" cy="30.6" r=".23"/>
<circle cx="245.2" cy="142.4" r=".23"/>
<circle cx="234.9" cy="110.2" r=".23"/>
<circle cx="237.3" cy="107.8" r=".23"/>
<circle cx="232.5" cy="116.3" r=".23"/>
<circle cx="227.6" cy="118.7" r=".23"/>
<circle cx="230.1" cy="117.5" r=".23"/>
<circle cx="252.5" cy="44" r=".23"/>
<circle cx="224.6" cy="43.4" r=".23"/>
<circle cx="210.6" cy="40.9" r=".23"/>
<circle cx="166.9" cy="112" r=".23"/>
<circle cx="155.9" cy="45.2" r=".23"/>
<circle cx="216.7" cy="84.7" r=".23"/>
<circle cx="36.2" cy="55.5" r=".23"/>
<circle cx="36.2" cy="36.7" r=".23"/>
<circle cx="33.8" cy="55.5" r=".23"/>
<circle cx="42.3" cy="55.5" r=".23"/>
<circle cx="42.3" cy="60.4" r=".23"/>
<circle cx="42.3" cy="59.2" r=".23"/>
<circle cx="42.3" cy="61.6" r=".23"/>
<circle cx="100.6" cy="85.3" r=".23"/>
<circle cx="185.7" cy="63.4" r=".23"/>
<circle cx="189.3" cy="63.4" r=".23"/>
<circle cx="185.7" cy="67.1" r=".23"/>
<circle cx="66.6" cy="94.4" r=".23"/>
<circle cx="62.9" cy="93.2" r=".23"/>
<circle cx="62.9" cy="90.8" r=".23"/>
<circle cx="55" cy="95.6" r=".23"/>
<circle cx="59.3" cy="92" r=".23"/>
<circle cx="66.6" cy="89.5" r=".23"/>
<circle cx="242.2" cy="83.5" r=".23"/>
<circle cx="237.3" cy="85.9" r=".23"/>
<circle cx="258.6" cy="38.5" r=".23"/>
<circle cx="256.2" cy="38.5" r=".23"/>
<circle cx="261" cy="38.5" r=".23"/>
<circle cx="264.1" cy="38.5" r=".23"/>
<circle cx="267.7" cy="38.5" r=".23"/>
<circle cx="188.1" cy="53.7" r=".23"/>
<circle cx="220.3" cy="111.4" r=".23"/>
<circle cx="211.2" cy="140.6" r=".23"/>
<circle cx="36.2" cy="26.9" r=".23"/>
<circle cx="62.9" cy="83.5" r=".23"/>
<circle cx="59.3" cy="83.5" r=".23"/>
<circle cx="55" cy="83.5" r=".23"/>
<circle cx="50.8" cy="83.5" r=".23"/>
<circle cx="66.6" cy="83.5" r=".23"/>
<circle cx="64.8" cy="124.2" r=".23"/>
<circle cx="192.4" cy="80.4" r=".23"/>
<circle cx="253.1" cy="93.2" r=".23"/>
<circle cx="179" cy="123.6" r=".23"/>
<circle cx="93.3" cy="53.7" r=".23"/>
<circle cx="93.3" cy="51.2" r=".23"/>
<circle cx="93.3" cy="52.5" r=".23"/>
<circle cx="189.9" cy="144.2" r=".23"/>
<circle cx="184.5" cy="105.9" r=".23"/>
<circle cx="184.5" cy="103.5" r=".23"/>
</g>
<g fill="none" stroke="#008000" stroke-width=".13">
<path d="M35 26.9h1.2v3.7h1.2M36.2 36.7h1.2M36.2 26.9h.6M37.4 33h-1.2v29.8M41.7 26.9h.6v3.7M42.3 30.6v6.1h-1.2M42.3 30.6h9.7M56.9 30.6h3.6v1.2M60.5 36.7v3.6M60.5 30.6h4.9M63 34.2h2.4M64.2 34.2v.7"/>
<path d="M64.2 39.7v.6M70.2 30.6h1.3v3.6h-1.3M71.5 34.2h4.2M154.1 36.7v.6M155.9 36.7v.6M168.7 35.5h-1.2v2.4h6M172.3 35.5h1.2M188.1 39.1h4.9M188.1 36.7h4.9M196.6 36.7h3.7v2.4M196.6 39.1h3.7M200.3 39.1v1.2"/>
<path d="M209.4 39.7h1.2v1.2h-1.2M214.3 38.5h-1.3v1.2M216.7 36.1v-1.2h-6.1v3.6h-1.2M219.1 38.5h1.9M220.3 34.9v7.2M228.2 38.5h4.9v6.1M233.1 38.5h2.4v6.1M233.7 37.3h4.9M233.7 36.1h4.9M235.5 38.5h3.1M245.9 36.1h1.2v1.2M245.9 37.3h1.2v7.3"/>
<path d="M245.9 38.5h3M247.1 34.2v1.9M256.2 38.5h2.4M258.6 38.5h9.1v.6M258.6 38.5v.6M261 38.5v6.1M264.1 38.5v6.1M267.7 37.3v1.2M33.8 55.5h-4.9v3.7M36.8 55.5h-3v3.7M41.7 55.5h21.3M42.3 59.2h3"/>
<path d="M45.3 51.9h-3v13.3M47.8 49.4h5.4M47.8 48.2h5.4M50.2 59.2h12.8M50.2 51.9h12.8M52.6 56.7h10.4M52.6 53.1h10.4M58.1 49.4h4.9M58.1 48.2h4.9M60.5 58h2.5M63 54.3h-2.5v15.8M63 45.2h-1.3v3"/>
<path d="M67.8 45.2h4.9M77.6 52.5h9.7M77.6 53.7h7.2M81.2 51.3h-3.6v13.3h7.8M83 57.3h.6M83.6 50h-6v1.3M84.8 51.3h21.9M87.3 48.8h-9.7v1.2M88.5 57.3h1.2v4.9h-3.7M88.5 53.7h18.2M90.9 52.5h15.8M90.9 48.8h6.1"/>
<path d="M93.3 47v6.7M97 55.5v-.6h8.5v1.2M97 54.9h-3.7v.6M97 47v1.8M100.6 47v3M103.7 57.3h1.8v1.2h1.2M104.3 42.1v1.9h2.4M106.7 56.1h-1.2v1.2h1.2M106.7 48.8h-1.2v1.2h-18.2M106.7 46.4h-2.4v2.4h-7.3M150.5 51.3h6M150.5 52.5h6"/>
<path d="M150.5 53.7h6M150.5 57.3h15.8M150.5 48.8h6M150.5 46.4h23M150.5 47.6h8.5v2.4h14.5M150.5 44h6M150.5 54.9h6M150.5 45.2h5.4M150.5 58.5h6M150.5 50h6M150.5 56.1h15.8M150.5 59.8h6"/>
<path d="M154.1 42.1v1.9M155.9 42.1v3.1h.6M168.7 40.3h-1.2v2.5h6M171.1 57.3h1.2M171.1 56.1h1.2M172.3 40.3h1.2M173.5 48.8h-1.2v4.3h6.1v9.1M187.5 53.7h1.2M188.1 53.7v3.6h2.5M188.1 48.8h3.1M188.1 46.4h3.1M191.2 47.6h-1.8v2.4h-1.3"/>
<path d="M194.2 57.3h3M196 53.7h1.2v4.3M198.5 47.6h1.8v12.2M203.9 58.5v1.3M205.1 58.5v6.1h3.1v-1.2M208.2 57.3v1.2M210.6 40.9v1.9h6.1v-1.9M218.5 47h1.8M220.3 45.8v3M224 57.3v1.2M224.6 42.1v2.5M224.6 47v1.8"/>
<path d="M224.6 43.4h5.5M229.5 44.6v2.4M233.1 48.2v.6M235.5 48.2v.6M247.1 48.2v.6M252.5 42.1v1.9h6.1M261 48.2v.6M264.1 48.2v.6M267.7 42.8v.3M267.7 47.9v.9M28.9 64v6.1M33.8 64v1.2"/>
<path d="M33.8 68.9v1.2M36.2 66.5v3.6M42.3 68.9v1.2M42.3 60.4h3M42.3 61.6h3M47.8 64h5.4M47.8 65.2h5.4M50.2 60.4h12.8M50.2 61.6h12.8M58.1 64h4.9M58.1 65.2h4.9M61.7 64v5.5h11.6"/>
<path d="M77.6 61h7.8M77.6 62.2h4.8M77.6 63.4h1.8M77.6 65.8h4.8M77.6 67.1h1.8M77.6 64.6v4.9M89.1 61h17.6M89.7 67.1h17M94.5 74.4h1.3M94.5 74.4v2.4M94.5 72.5h8.6M95.8 76.8h-1.3v3.6"/>
<path d="M95.8 70.7h-1.3v3.7M99.4 76.8h6.1v.6M99.4 74.4h7.3M99.4 70.7h7.3M105.5 79.8v.6h-6.1M105.5 76.8h1.2M105.5 70.7v.6M105.5 73.7v.7M106.7 62.2h-17v1.2h-6.7M106.7 63.4h-17v1.2h-.6M106.7 64.6h-17v1.2h-3.7M106.7 65.8h-17v1.3h-6.7"/>
<path d="M150.5 61h6M150.5 62.2h6M150.5 63.4h6M150.5 64.6h6M150.5 65.8h6M150.5 67.1h6M150.5 69.5h6M150.5 79.2h6M150.5 74.4h6M150.5 75.6h6M150.5 68.3h6M150.5 70.7h6"/>
<path d="M150.5 76.8h15.1M150.5 71.9h6M150.5 73.1h6M150.5 78h15.1M166.9 67.1h1.2M170.5 76.8h2.4M170.5 78h2.4M172.9 70.7v1.2M177.8 67.1h7.9M182.1 62.2v1.2h-1.3M183.3 62.2v1.2h2.4M185.7 63.4h3.7v2.4"/>
<path d="M185.7 63.4v9.7h-9.1M185.7 62.2v1.2M189.4 63.4h2.4v1.2M189.4 69.5v2.4M191.8 70.7v1.2M192.4 79.8v.6M200.3 64.6v2.5h1.2M200.3 67.1v1.2M200.3 70.7v1.2M203.9 69.5v2.4M208.2 64.6v11h-31.6M224 68.9v2.4h-4.9"/>
<path d="M224 63.4v1.8M230.7 74.4h11.5v3h-1.2M230.7 71.9h6.7M241 79.8h1.2v1.2M242.2 68.3v3.6h-1.2M246.5 68.3v.6h1.2M246.5 76.2v2.4h-5.5M246.5 61v2.4M246.5 68.9v2.4M250.1 63.4v3.1M250.1 79.8v3.7M251.9 71.3h-1.8v3.7"/>
<path d="M257.4 73.1v7.9h1.2M42.3 99.3h1.2M42.3 90.8h1.2M42.3 92h1.2M42.3 93.2h1.2M42.3 94.4h1.2M42.3 95.6h1.2M42.3 96.8h1.2M42.3 98.1h1.2M43.5 89.6h-1.2v15.7M50.8 99.3h4.3v1.2M50.8 98.1h8.5v2.4"/>
<path d="M50.8 93.2h12.2v7.3M50.8 83.5h-8.5v4.8h1.2M50.8 90.8h12.2M50.8 92h8.5M50.8 94.4h15.8M50.8 95.6h4.3M55.1 88.9v6.7h17.6l1.2-1.2M55.1 84.1v-.6h-4.3v4.8M55.1 83.5h4.2v.6M55.1 99.3h3M59.3 88.9v3.1h13.4l1.2-1.2M59.3 83.5h3.7v.6"/>
<path d="M63 88.9v1.9h9.7l1.2-1.2M63 83.5h3.6v.6M66.6 88.9v.7h-15.8M67.8 99.3h-1.2v1.2M73.9 93.2l-1.2 1.2h-6.1v3.7h1.2M73.9 92l-1.2 1.2h-9.7M73.9 95.6l-1.2 1.2h-21.9M73.9 88.3l-1.2 1.3h-6.1M81.2 96.2h25.5M81.2 86.5v2.4M81.2 93.8v3M88.5 84.1l1.2 1.2h17"/>
<path d="M88.5 86.5l1.2 1.2h17M88.5 87.7l1.2 1.2h17M88.5 91.4l1.2 1.2h17M88.5 92.6l1.2 1.2h17M88.5 90.1l1.2 1.3h17M88.5 88.9l1.2 1.2h17M95.8 80.4h-1.3v.6M97.6 98.7h9.1M98.2 84.1h2.4v1.2M100.6 86.5h6.1M105.5 80.4h1.2M150.5 88.9h17.6l1.2 1.2"/>
<path d="M150.5 93.8h17.6l1.2 1.2 1.2-1.2h4.9M150.5 95h17.6l1.2 1.2M150.5 96.2h17.6l1.2 1.3M150.5 90.1h17.6l1.2 1.3M150.5 91.4h17.6l1.2 1.2M150.5 92.6h17.6l1.2 1.2M150.5 85.3h17.6l1.2 1.2M150.5 86.5h17.6l1.2 1.2 1.2-1.2h8.5M150.5 87.7h17.6l1.2 1.2M150.5 98.7h6.6M150.5 80.4h6M150.5 97.5h6.6"/>
<path d="M150.5 99.9h6.6M150.5 81.6h6M150.5 82.9h6M166.9 98.7v5.4M173.5 93.8v1.8M180.2 93.8h1.3M181.8 80.4h-2.8v3.7M185.7 98.1h-1.2v7.9M186.6 80.4h5.8v3.7h-1.2M190.6 98.1h1.8v10.9M191.2 88.9h1.2v.7M197.2 96.8v-1.2h4.9v1.2"/>
<path d="M197.2 95.6h-18.8v12.8M198.5 84.7h2.4v1.8M200.9 84.7h.6M200.9 90.1v.7M206.4 84.7h3M209.4 96.8v6.7h-12.2v5.5M214.3 84.7h2.4v1.8M216.7 84.7h.6M216.7 90.1v.7M222.2 84.7h3M222.8 96.8v25.6h-11M227.6 96.8v.7h2.5v1.8"/>
<path d="M227.6 97.5v1.8M230.1 97.5h2.4v1.8M230.7 83.5h11.5M230.7 85.9h6.7M234.9 99.3v-1.8h2.5v1.8M236.1 96.8v12.2h1.9M237.4 97.5h6.6v1.2M243.4 83.5h-1.2v3.6M243.4 85.9h-6v1.2M248.3 83.5h10.3M252.5 93.2h8.5M253.2 93.2v5.2"/>
<path d="M257.4 99.3h3.6M257.4 95.6h3.6M257.4 96.8h3.6M257.4 98.1h3.6M258.6 82.3h-4.8v3.6h-5.5M258.6 84.7h-3v6.1M261 94.4h-6v1.8M49 119.3h1.2M62.4 119.3h9.1l1.2 1.2M80 107.8h1.8M80 112.6h1.8M80.6 119.3h1.2"/>
<path d="M80.6 105.3h1.2M80.6 110.2h1.2M81.2 116.9h.6M98.2 106h8.5M98.2 107.2h8.5M150.5 115.7h9.7l1.2 1.2M150.5 116.9h9.7l1.2 1.2M150.5 118.1h9.7l1.2 1.2M150.5 119.3h9.7l1.2 1.2M150.5 103.5h6.6M150.5 106h6.6M150.5 107.2h6.6"/>
<path d="M150.5 110.8h6.6M150.5 113.2h6.6M150.5 101.1h6.6M150.5 102.3h6.6M150.5 104.7h6.6M150.5 108.4h6.6M150.5 112h16.4M150.5 109.6h6.6M166.9 109v4.2M166.9 118.1v1.8M172.3 115.1v1.2h10.4M172.3 116.3h-1.8l-1.2 1.2"/>
<path d="M172.3 109v1.2M173.5 100.5v.6h21.3v7.9M178.4 103.5h1.8M178.4 106h1.8M182.7 117.5h-12.2l-1.2 1.2M183.9 106h7.3v3M183.9 103.5h.6M185.1 108.4h4.9v.6M194.8 101.1h6.1v7.9M196 101.1v7.9M197.2 100.5v3h-5.4M202.1 100.5v8.5"/>
<path d="M205.5 107.8h-2.2v1.2M210.3 107.8h4v.6M211.8 116.3h.6v1.2h-.6M212.4 116.3h1.9M214.3 113.2v4.3M217.3 118.7v4.9h-5.5M217.3 110.2v3.7M220.3 111.4v2.5h17.7M220.3 110.2v1.2M220.3 111.4h17.7M227.6 104.1v14.6M230.1 104.1v18.9"/>
<path d="M230.1 117.5h7.9M232.5 104.1v12.2h-12.2v3.6h-8.5M232.5 116.3h5.5M234.9 104.1v6.1h-10.9v-4.2h-24.3v3M234.9 110.2h3.1M237.4 104.1v3.7h.6M237.4 107.8h-12.2v-3.1h-26.7v4.3M238 118.7h-16.5v2.5h-9.7M238 112.6h-13.4v16.5h-4.3v-3.1M238 115.1h-11.6v17h-6.1M244 102.3v1.5M253.2 103.2v.9h7.8"/>
<path d="M257.4 100.5h3.6M257.4 101.7h3.6M257.4 102.9h3.6M41.7 120.5l1.2 1.3h7.3M41.7 123l1.2 1.2h7.3M41.7 124.2l1.2 1.2h7.3M41.7 126.6l1.2 1.2h7.3M41.7 121.8l1.2 1.2h7.3M41.7 125.4l1.2 1.2h7.3M41.7 127.8l1.2 1.3h7.3M47.8 138.8h2.4M47.8 137.6h2.4"/>
<path d="M47.8 136.3h2.4M47.8 135.1h2.4M47.8 131.5h2.4M47.8 132.7h2.4M47.8 133.9h2.4M50.2 130.3h-2.4v22.4M62.4 125.4h5.4v1.2M62.4 138.8h9.1l1.2 1.2 1.2-1.2h10.3M62.4 137.6h9.1l1.2 1.2 1.2-1.2h10.3M62.4 130.3h9.1l1.2 1.2 1.2-1.2h10.3M62.4 136.3h9.1l1.2 1.3 1.2-1.3h10.3M62.4 131.5h9.1l1.2 1.2 1.2-1.2h10.3"/>
<path d="M62.4 135.1h9.1l1.2 1.2 1.2-1.2h10.3M62.4 132.7h9.1l1.2 1.2 1.2-1.2h10.3M62.4 133.9h9.1l1.2 1.2 1.2-1.2h10.3M62.4 121.8h9.1l1.2 1.2M62.4 123h2.4v1.2M62.4 124.2h3.6M64.8 125.4v1.2h-2.4M64.8 126.6v1.2h-2.4M64.8 127.8v1.3h-2.4M81.2 124.2h.6M84.2 127.8h-10.3l-1.2 1.3M84.2 129.1h-10.3l-1.2 1.2"/>
<path d="M104.9 140h1.8M104.9 138.8h1.8M104.9 137.6h1.8M104.9 136.3h1.8M106.7 135.1h-1.8v13.4M150.5 120.5h9.7l1.2 1.3M150.5 121.8h9.7l1.2 1.2M150.5 123h9.7l1.2 1.2M150.5 124.2h9.7l1.2 1.2M150.5 125.4h9.7l1.2 1.2M150.5 126.6h9.7l1.2 1.2M150.5 131.5h7.3"/>
<path d="M150.5 127.8h7.3M150.5 129.1h7.3M150.5 130.3h7.3M178.4 123.6h4.3M179 123.6v9.1M179 136.3v12.2M182.7 126h-12.2l-1.2 1.2M182.7 122.4h-12.2l-1.2 1.2M182.7 121.2h-12.2l-1.2 1.2M182.7 128.4h-12.2l-1.2 1.3M182.7 129.7h-1.2v18.8M182.7 124.8h-1.2v4.9"/>
<path d="M190 139.4v4.9h-4.3M192.4 139.4v10.9l-1.2 1.2M193.6 139.4v10.9l-1.2 1.2M194.8 139.4v10.9l-1.2 1.2M196 139.4v10.9l-1.2 1.2M199.7 139.4v3.6M202.1 139.4v2.4h4.3v6.7M203.3 139.4v1.2h7.9M211.2 139.4v3M211.8 127.2h3.1v1.9h.6M211.8 128.4h1.9v3.7h1.8M211.8 129.7h.6v5.4h3.1"/>
<path d="M211.8 126h3.7M220.3 135.1h6.1M230.1 126.6v1.2M232.5 139.4v8.5h.6M235.5 138.2h1.2M241.6 138.2h3.7v7.3h-1.3M53.8 147.3v3.6h2.5v-3.6M55.1 147.3v3.6M57.5 147.3v3.6M58.7 147.3v3.6h-2.4v1.8M63.6 146.1h1.2v1.2M64.8 152.1v.6"/>
<path d="M72.7 143.6l-1.2-1.2h-6.7v2.4h-1.2M104.9 142.4h1.8M104.9 147.3h1.8M104.9 144.8h1.8M104.9 143.6h1.8M104.9 141.2h1.8M150.5 147.3h7.9M150.5 144.8h7.9M150.5 143.6h7.9M150.5 146.1h7.9M172.3 141.2h10.4M181.5 144.3h.6"/>
<path d="M181.5 146.7h.6M190 144.3v2.4h-4.3M211.2 146.1v2.4M223.4 149.1h2.4M223.4 145.5h9.7M227.6 146.7h5.5M230.7 144.8v1.9M230.7 149.1h2.4M232.5 140.6h-1.8v.6M232.5 142.4h4.2M241.6 142.4h3.7M254.4 141.8h-1.9v-3.6h-5.4v8.5h-3.1"/>
<path d="M254.4 143h-1.9v4.9h-8.5M254.4 144.3h-.6v6"/>
</g>
<use href="#words"/>
</svg>
